VERSION 5.8 ;
BUSBITCHARS "[]" ;
DIVIDERCHAR "/" ;
UNITS
    DATABASE MICRONS 1000 ;
END UNITS

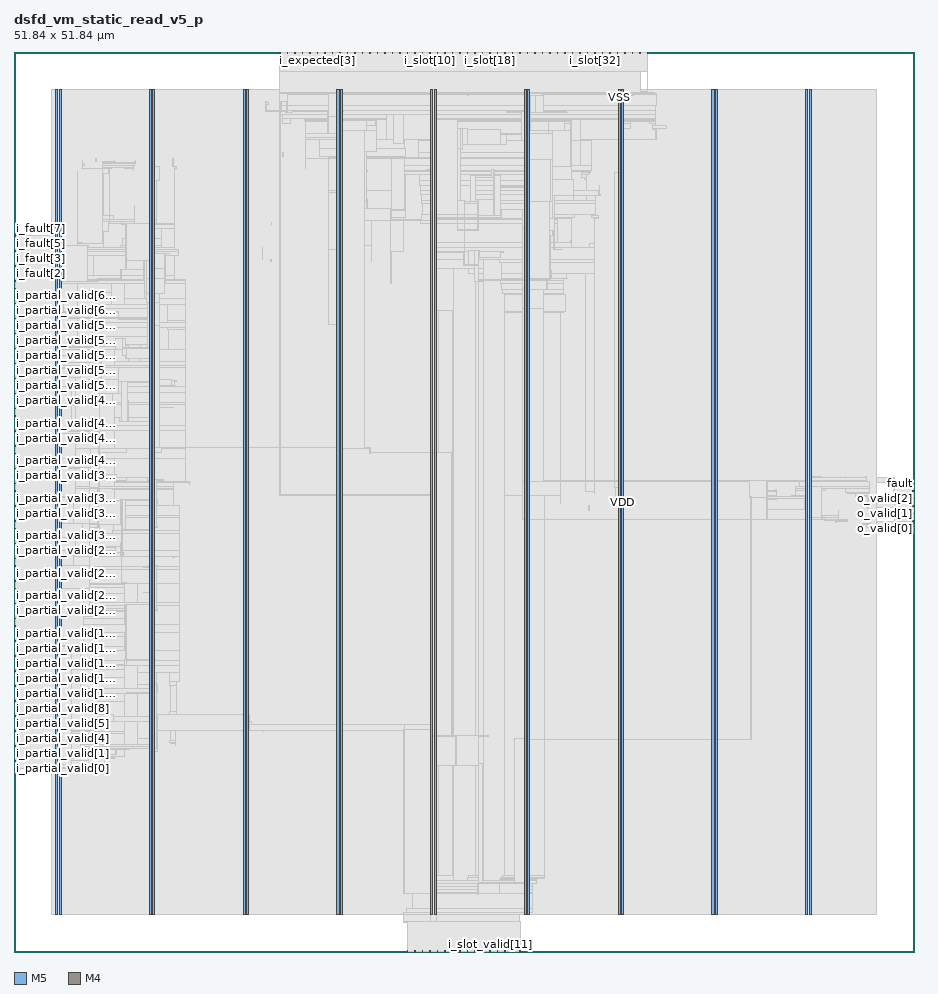
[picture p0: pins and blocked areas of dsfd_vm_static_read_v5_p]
MACRO dsfd_vm_static_read_v5_p
  FOREIGN dsfd_vm_static_read_v5_p 0 0 ;
  CLASS BLOCK ;
  SIZE 51.84 BY 51.84 ;
  PIN ck
    DIRECTION INPUT ;
    USE SIGNAL ;
    PORT
      LAYER M5 ;
        RECT  15.312 51.756 15.336 51.84 ;
    END
  END ck
  PIN fault
    DIRECTION OUTPUT ;
    USE SIGNAL ;
    PORT
      LAYER M4 ;
        RECT  51.756 26.976 51.84 27 ;
    END
  END fault
  PIN i_expected[0]
    DIRECTION INPUT ;
    USE SIGNAL ;
    PORT
      LAYER M5 ;
        RECT  16.176 51.756 16.2 51.84 ;
    END
  END i_expected[0]
  PIN i_expected[1]
    DIRECTION INPUT ;
    USE SIGNAL ;
    PORT
      LAYER M5 ;
        RECT  16.608 51.756 16.632 51.84 ;
    END
  END i_expected[1]
  PIN i_expected[2]
    DIRECTION INPUT ;
    USE SIGNAL ;
    PORT
      LAYER M5 ;
        RECT  17.04 51.756 17.064 51.84 ;
    END
  END i_expected[2]
  PIN i_expected[3]
    DIRECTION INPUT ;
    USE SIGNAL ;
    PORT
      LAYER M5 ;
        RECT  17.472 51.756 17.496 51.84 ;
    END
  END i_expected[3]
  PIN i_expected[4]
    DIRECTION INPUT ;
    USE SIGNAL ;
    PORT
      LAYER M5 ;
        RECT  17.904 51.756 17.928 51.84 ;
    END
  END i_expected[4]
  PIN i_expected[5]
    DIRECTION INPUT ;
    USE SIGNAL ;
    PORT
      LAYER M5 ;
        RECT  18.336 51.756 18.36 51.84 ;
    END
  END i_expected[5]
  PIN i_expected[6]
    DIRECTION INPUT ;
    USE SIGNAL ;
    PORT
      LAYER M5 ;
        RECT  18.768 51.756 18.792 51.84 ;
    END
  END i_expected[6]
  PIN i_expected[7]
    DIRECTION INPUT ;
    USE SIGNAL ;
    PORT
      LAYER M5 ;
        RECT  19.2 51.756 19.224 51.84 ;
    END
  END i_expected[7]
  PIN i_fault[0]
    DIRECTION INPUT ;
    USE SIGNAL ;
    PORT
      LAYER M4 ;
        RECT  0 38.208 0.084 38.232 ;
    END
  END i_fault[0]
  PIN i_fault[1]
    DIRECTION INPUT ;
    USE SIGNAL ;
    PORT
      LAYER M4 ;
        RECT  0 38.64 0.084 38.664 ;
    END
  END i_fault[1]
  PIN i_fault[2]
    DIRECTION INPUT ;
    USE SIGNAL ;
    PORT
      LAYER M4 ;
        RECT  0 39.072 0.084 39.096 ;
    END
  END i_fault[2]
  PIN i_fault[3]
    DIRECTION INPUT ;
    USE SIGNAL ;
    PORT
      LAYER M4 ;
        RECT  0 39.504 0.084 39.528 ;
    END
  END i_fault[3]
  PIN i_fault[4]
    DIRECTION INPUT ;
    USE SIGNAL ;
    PORT
      LAYER M4 ;
        RECT  0 39.936 0.084 39.96 ;
    END
  END i_fault[4]
  PIN i_fault[5]
    DIRECTION INPUT ;
    USE SIGNAL ;
    PORT
      LAYER M4 ;
        RECT  0 40.368 0.084 40.392 ;
    END
  END i_fault[5]
  PIN i_fault[6]
    DIRECTION INPUT ;
    USE SIGNAL ;
    PORT
      LAYER M4 ;
        RECT  0 40.8 0.084 40.824 ;
    END
  END i_fault[6]
  PIN i_fault[7]
    DIRECTION INPUT ;
    USE SIGNAL ;
    PORT
      LAYER M4 ;
        RECT  0 41.232 0.084 41.256 ;
    END
  END i_fault[7]
  PIN i_partial_valid[0]
    DIRECTION INPUT ;
    USE SIGNAL ;
    PORT
      LAYER M4 ;
        RECT  0 10.56 0.084 10.584 ;
    END
  END i_partial_valid[0]
  PIN i_partial_valid[10]
    DIRECTION INPUT ;
    USE SIGNAL ;
    PORT
      LAYER M4 ;
        RECT  0 14.88 0.084 14.904 ;
    END
  END i_partial_valid[10]
  PIN i_partial_valid[11]
    DIRECTION INPUT ;
    USE SIGNAL ;
    PORT
      LAYER M4 ;
        RECT  0 15.312 0.084 15.336 ;
    END
  END i_partial_valid[11]
  PIN i_partial_valid[12]
    DIRECTION INPUT ;
    USE SIGNAL ;
    PORT
      LAYER M4 ;
        RECT  0 15.744 0.084 15.768 ;
    END
  END i_partial_valid[12]
  PIN i_partial_valid[13]
    DIRECTION INPUT ;
    USE SIGNAL ;
    PORT
      LAYER M4 ;
        RECT  0 16.176 0.084 16.2 ;
    END
  END i_partial_valid[13]
  PIN i_partial_valid[14]
    DIRECTION INPUT ;
    USE SIGNAL ;
    PORT
      LAYER M4 ;
        RECT  0 16.608 0.084 16.632 ;
    END
  END i_partial_valid[14]
  PIN i_partial_valid[15]
    DIRECTION INPUT ;
    USE SIGNAL ;
    PORT
      LAYER M4 ;
        RECT  0 17.04 0.084 17.064 ;
    END
  END i_partial_valid[15]
  PIN i_partial_valid[16]
    DIRECTION INPUT ;
    USE SIGNAL ;
    PORT
      LAYER M4 ;
        RECT  0 17.472 0.084 17.496 ;
    END
  END i_partial_valid[16]
  PIN i_partial_valid[17]
    DIRECTION INPUT ;
    USE SIGNAL ;
    PORT
      LAYER M4 ;
        RECT  0 17.904 0.084 17.928 ;
    END
  END i_partial_valid[17]
  PIN i_partial_valid[18]
    DIRECTION INPUT ;
    USE SIGNAL ;
    PORT
      LAYER M4 ;
        RECT  0 18.336 0.084 18.36 ;
    END
  END i_partial_valid[18]
  PIN i_partial_valid[19]
    DIRECTION INPUT ;
    USE SIGNAL ;
    PORT
      LAYER M4 ;
        RECT  0 18.768 0.084 18.792 ;
    END
  END i_partial_valid[19]
  PIN i_partial_valid[1]
    DIRECTION INPUT ;
    USE SIGNAL ;
    PORT
      LAYER M4 ;
        RECT  0 10.992 0.084 11.016 ;
    END
  END i_partial_valid[1]
  PIN i_partial_valid[20]
    DIRECTION INPUT ;
    USE SIGNAL ;
    PORT
      LAYER M4 ;
        RECT  0 19.2 0.084 19.224 ;
    END
  END i_partial_valid[20]
  PIN i_partial_valid[21]
    DIRECTION INPUT ;
    USE SIGNAL ;
    PORT
      LAYER M4 ;
        RECT  0 19.632 0.084 19.656 ;
    END
  END i_partial_valid[21]
  PIN i_partial_valid[22]
    DIRECTION INPUT ;
    USE SIGNAL ;
    PORT
      LAYER M4 ;
        RECT  0 20.064 0.084 20.088 ;
    END
  END i_partial_valid[22]
  PIN i_partial_valid[23]
    DIRECTION INPUT ;
    USE SIGNAL ;
    PORT
      LAYER M4 ;
        RECT  0 20.496 0.084 20.52 ;
    END
  END i_partial_valid[23]
  PIN i_partial_valid[24]
    DIRECTION INPUT ;
    USE SIGNAL ;
    PORT
      LAYER M4 ;
        RECT  0 20.928 0.084 20.952 ;
    END
  END i_partial_valid[24]
  PIN i_partial_valid[25]
    DIRECTION INPUT ;
    USE SIGNAL ;
    PORT
      LAYER M4 ;
        RECT  0 21.36 0.084 21.384 ;
    END
  END i_partial_valid[25]
  PIN i_partial_valid[26]
    DIRECTION INPUT ;
    USE SIGNAL ;
    PORT
      LAYER M4 ;
        RECT  0 21.792 0.084 21.816 ;
    END
  END i_partial_valid[26]
  PIN i_partial_valid[27]
    DIRECTION INPUT ;
    USE SIGNAL ;
    PORT
      LAYER M4 ;
        RECT  0 22.224 0.084 22.248 ;
    END
  END i_partial_valid[27]
  PIN i_partial_valid[28]
    DIRECTION INPUT ;
    USE SIGNAL ;
    PORT
      LAYER M4 ;
        RECT  0 22.656 0.084 22.68 ;
    END
  END i_partial_valid[28]
  PIN i_partial_valid[29]
    DIRECTION INPUT ;
    USE SIGNAL ;
    PORT
      LAYER M4 ;
        RECT  0 23.088 0.084 23.112 ;
    END
  END i_partial_valid[29]
  PIN i_partial_valid[2]
    DIRECTION INPUT ;
    USE SIGNAL ;
    PORT
      LAYER M4 ;
        RECT  0 11.424 0.084 11.448 ;
    END
  END i_partial_valid[2]
  PIN i_partial_valid[30]
    DIRECTION INPUT ;
    USE SIGNAL ;
    PORT
      LAYER M4 ;
        RECT  0 23.52 0.084 23.544 ;
    END
  END i_partial_valid[30]
  PIN i_partial_valid[31]
    DIRECTION INPUT ;
    USE SIGNAL ;
    PORT
      LAYER M4 ;
        RECT  0 23.952 0.084 23.976 ;
    END
  END i_partial_valid[31]
  PIN i_partial_valid[32]
    DIRECTION INPUT ;
    USE SIGNAL ;
    PORT
      LAYER M4 ;
        RECT  0 24.384 0.084 24.408 ;
    END
  END i_partial_valid[32]
  PIN i_partial_valid[33]
    DIRECTION INPUT ;
    USE SIGNAL ;
    PORT
      LAYER M4 ;
        RECT  0 24.816 0.084 24.84 ;
    END
  END i_partial_valid[33]
  PIN i_partial_valid[34]
    DIRECTION INPUT ;
    USE SIGNAL ;
    PORT
      LAYER M4 ;
        RECT  0 25.248 0.084 25.272 ;
    END
  END i_partial_valid[34]
  PIN i_partial_valid[35]
    DIRECTION INPUT ;
    USE SIGNAL ;
    PORT
      LAYER M4 ;
        RECT  0 25.68 0.084 25.704 ;
    END
  END i_partial_valid[35]
  PIN i_partial_valid[36]
    DIRECTION INPUT ;
    USE SIGNAL ;
    PORT
      LAYER M4 ;
        RECT  0 26.112 0.084 26.136 ;
    END
  END i_partial_valid[36]
  PIN i_partial_valid[37]
    DIRECTION INPUT ;
    USE SIGNAL ;
    PORT
      LAYER M4 ;
        RECT  0 26.544 0.084 26.568 ;
    END
  END i_partial_valid[37]
  PIN i_partial_valid[38]
    DIRECTION INPUT ;
    USE SIGNAL ;
    PORT
      LAYER M4 ;
        RECT  0 26.976 0.084 27 ;
    END
  END i_partial_valid[38]
  PIN i_partial_valid[39]
    DIRECTION INPUT ;
    USE SIGNAL ;
    PORT
      LAYER M4 ;
        RECT  0 27.408 0.084 27.432 ;
    END
  END i_partial_valid[39]
  PIN i_partial_valid[3]
    DIRECTION INPUT ;
    USE SIGNAL ;
    PORT
      LAYER M4 ;
        RECT  0 11.856 0.084 11.88 ;
    END
  END i_partial_valid[3]
  PIN i_partial_valid[40]
    DIRECTION INPUT ;
    USE SIGNAL ;
    PORT
      LAYER M4 ;
        RECT  0 27.84 0.084 27.864 ;
    END
  END i_partial_valid[40]
  PIN i_partial_valid[41]
    DIRECTION INPUT ;
    USE SIGNAL ;
    PORT
      LAYER M4 ;
        RECT  0 28.272 0.084 28.296 ;
    END
  END i_partial_valid[41]
  PIN i_partial_valid[42]
    DIRECTION INPUT ;
    USE SIGNAL ;
    PORT
      LAYER M4 ;
        RECT  0 28.704 0.084 28.728 ;
    END
  END i_partial_valid[42]
  PIN i_partial_valid[43]
    DIRECTION INPUT ;
    USE SIGNAL ;
    PORT
      LAYER M4 ;
        RECT  0 29.136 0.084 29.16 ;
    END
  END i_partial_valid[43]
  PIN i_partial_valid[44]
    DIRECTION INPUT ;
    USE SIGNAL ;
    PORT
      LAYER M4 ;
        RECT  0 29.568 0.084 29.592 ;
    END
  END i_partial_valid[44]
  PIN i_partial_valid[45]
    DIRECTION INPUT ;
    USE SIGNAL ;
    PORT
      LAYER M4 ;
        RECT  0 30 0.084 30.024 ;
    END
  END i_partial_valid[45]
  PIN i_partial_valid[46]
    DIRECTION INPUT ;
    USE SIGNAL ;
    PORT
      LAYER M4 ;
        RECT  0 30.432 0.084 30.456 ;
    END
  END i_partial_valid[46]
  PIN i_partial_valid[47]
    DIRECTION INPUT ;
    USE SIGNAL ;
    PORT
      LAYER M4 ;
        RECT  0 30.864 0.084 30.888 ;
    END
  END i_partial_valid[47]
  PIN i_partial_valid[48]
    DIRECTION INPUT ;
    USE SIGNAL ;
    PORT
      LAYER M4 ;
        RECT  0 31.296 0.084 31.32 ;
    END
  END i_partial_valid[48]
  PIN i_partial_valid[49]
    DIRECTION INPUT ;
    USE SIGNAL ;
    PORT
      LAYER M4 ;
        RECT  0 31.728 0.084 31.752 ;
    END
  END i_partial_valid[49]
  PIN i_partial_valid[4]
    DIRECTION INPUT ;
    USE SIGNAL ;
    PORT
      LAYER M4 ;
        RECT  0 12.288 0.084 12.312 ;
    END
  END i_partial_valid[4]
  PIN i_partial_valid[50]
    DIRECTION INPUT ;
    USE SIGNAL ;
    PORT
      LAYER M4 ;
        RECT  0 32.16 0.084 32.184 ;
    END
  END i_partial_valid[50]
  PIN i_partial_valid[51]
    DIRECTION INPUT ;
    USE SIGNAL ;
    PORT
      LAYER M4 ;
        RECT  0 32.592 0.084 32.616 ;
    END
  END i_partial_valid[51]
  PIN i_partial_valid[52]
    DIRECTION INPUT ;
    USE SIGNAL ;
    PORT
      LAYER M4 ;
        RECT  0 33.024 0.084 33.048 ;
    END
  END i_partial_valid[52]
  PIN i_partial_valid[53]
    DIRECTION INPUT ;
    USE SIGNAL ;
    PORT
      LAYER M4 ;
        RECT  0 33.456 0.084 33.48 ;
    END
  END i_partial_valid[53]
  PIN i_partial_valid[54]
    DIRECTION INPUT ;
    USE SIGNAL ;
    PORT
      LAYER M4 ;
        RECT  0 33.888 0.084 33.912 ;
    END
  END i_partial_valid[54]
  PIN i_partial_valid[55]
    DIRECTION INPUT ;
    USE SIGNAL ;
    PORT
      LAYER M4 ;
        RECT  0 34.32 0.084 34.344 ;
    END
  END i_partial_valid[55]
  PIN i_partial_valid[56]
    DIRECTION INPUT ;
    USE SIGNAL ;
    PORT
      LAYER M4 ;
        RECT  0 34.752 0.084 34.776 ;
    END
  END i_partial_valid[56]
  PIN i_partial_valid[57]
    DIRECTION INPUT ;
    USE SIGNAL ;
    PORT
      LAYER M4 ;
        RECT  0 35.184 0.084 35.208 ;
    END
  END i_partial_valid[57]
  PIN i_partial_valid[58]
    DIRECTION INPUT ;
    USE SIGNAL ;
    PORT
      LAYER M4 ;
        RECT  0 35.616 0.084 35.64 ;
    END
  END i_partial_valid[58]
  PIN i_partial_valid[59]
    DIRECTION INPUT ;
    USE SIGNAL ;
    PORT
      LAYER M4 ;
        RECT  0 36.048 0.084 36.072 ;
    END
  END i_partial_valid[59]
  PIN i_partial_valid[5]
    DIRECTION INPUT ;
    USE SIGNAL ;
    PORT
      LAYER M4 ;
        RECT  0 12.72 0.084 12.744 ;
    END
  END i_partial_valid[5]
  PIN i_partial_valid[60]
    DIRECTION INPUT ;
    USE SIGNAL ;
    PORT
      LAYER M4 ;
        RECT  0 36.48 0.084 36.504 ;
    END
  END i_partial_valid[60]
  PIN i_partial_valid[61]
    DIRECTION INPUT ;
    USE SIGNAL ;
    PORT
      LAYER M4 ;
        RECT  0 36.912 0.084 36.936 ;
    END
  END i_partial_valid[61]
  PIN i_partial_valid[62]
    DIRECTION INPUT ;
    USE SIGNAL ;
    PORT
      LAYER M4 ;
        RECT  0 37.344 0.084 37.368 ;
    END
  END i_partial_valid[62]
  PIN i_partial_valid[63]
    DIRECTION INPUT ;
    USE SIGNAL ;
    PORT
      LAYER M4 ;
        RECT  0 37.776 0.084 37.8 ;
    END
  END i_partial_valid[63]
  PIN i_partial_valid[6]
    DIRECTION INPUT ;
    USE SIGNAL ;
    PORT
      LAYER M4 ;
        RECT  0 13.152 0.084 13.176 ;
    END
  END i_partial_valid[6]
  PIN i_partial_valid[7]
    DIRECTION INPUT ;
    USE SIGNAL ;
    PORT
      LAYER M4 ;
        RECT  0 13.584 0.084 13.608 ;
    END
  END i_partial_valid[7]
  PIN i_partial_valid[8]
    DIRECTION INPUT ;
    USE SIGNAL ;
    PORT
      LAYER M4 ;
        RECT  0 14.016 0.084 14.04 ;
    END
  END i_partial_valid[8]
  PIN i_partial_valid[9]
    DIRECTION INPUT ;
    USE SIGNAL ;
    PORT
      LAYER M4 ;
        RECT  0 14.448 0.084 14.472 ;
    END
  END i_partial_valid[9]
  PIN i_slot[0]
    DIRECTION INPUT ;
    USE SIGNAL ;
    PORT
      LAYER M5 ;
        RECT  19.632 51.756 19.656 51.84 ;
    END
  END i_slot[0]
  PIN i_slot[10]
    DIRECTION INPUT ;
    USE SIGNAL ;
    PORT
      LAYER M5 ;
        RECT  23.952 51.756 23.976 51.84 ;
    END
  END i_slot[10]
  PIN i_slot[11]
    DIRECTION INPUT ;
    USE SIGNAL ;
    PORT
      LAYER M5 ;
        RECT  24.384 51.756 24.408 51.84 ;
    END
  END i_slot[11]
  PIN i_slot[12]
    DIRECTION INPUT ;
    USE SIGNAL ;
    PORT
      LAYER M5 ;
        RECT  24.816 51.756 24.84 51.84 ;
    END
  END i_slot[12]
  PIN i_slot[13]
    DIRECTION INPUT ;
    USE SIGNAL ;
    PORT
      LAYER M5 ;
        RECT  25.248 51.756 25.272 51.84 ;
    END
  END i_slot[13]
  PIN i_slot[14]
    DIRECTION INPUT ;
    USE SIGNAL ;
    PORT
      LAYER M5 ;
        RECT  25.68 51.756 25.704 51.84 ;
    END
  END i_slot[14]
  PIN i_slot[15]
    DIRECTION INPUT ;
    USE SIGNAL ;
    PORT
      LAYER M5 ;
        RECT  26.112 51.756 26.136 51.84 ;
    END
  END i_slot[15]
  PIN i_slot[16]
    DIRECTION INPUT ;
    USE SIGNAL ;
    PORT
      LAYER M5 ;
        RECT  26.544 51.756 26.568 51.84 ;
    END
  END i_slot[16]
  PIN i_slot[17]
    DIRECTION INPUT ;
    USE SIGNAL ;
    PORT
      LAYER M5 ;
        RECT  26.976 51.756 27 51.84 ;
    END
  END i_slot[17]
  PIN i_slot[18]
    DIRECTION INPUT ;
    USE SIGNAL ;
    PORT
      LAYER M5 ;
        RECT  27.408 51.756 27.432 51.84 ;
    END
  END i_slot[18]
  PIN i_slot[19]
    DIRECTION INPUT ;
    USE SIGNAL ;
    PORT
      LAYER M5 ;
        RECT  27.84 51.756 27.864 51.84 ;
    END
  END i_slot[19]
  PIN i_slot[1]
    DIRECTION INPUT ;
    USE SIGNAL ;
    PORT
      LAYER M5 ;
        RECT  20.064 51.756 20.088 51.84 ;
    END
  END i_slot[1]
  PIN i_slot[20]
    DIRECTION INPUT ;
    USE SIGNAL ;
    PORT
      LAYER M5 ;
        RECT  28.272 51.756 28.296 51.84 ;
    END
  END i_slot[20]
  PIN i_slot[21]
    DIRECTION INPUT ;
    USE SIGNAL ;
    PORT
      LAYER M5 ;
        RECT  28.704 51.756 28.728 51.84 ;
    END
  END i_slot[21]
  PIN i_slot[22]
    DIRECTION INPUT ;
    USE SIGNAL ;
    PORT
      LAYER M5 ;
        RECT  29.136 51.756 29.16 51.84 ;
    END
  END i_slot[22]
  PIN i_slot[23]
    DIRECTION INPUT ;
    USE SIGNAL ;
    PORT
      LAYER M5 ;
        RECT  29.568 51.756 29.592 51.84 ;
    END
  END i_slot[23]
  PIN i_slot[24]
    DIRECTION INPUT ;
    USE SIGNAL ;
    PORT
      LAYER M5 ;
        RECT  30 51.756 30.024 51.84 ;
    END
  END i_slot[24]
  PIN i_slot[25]
    DIRECTION INPUT ;
    USE SIGNAL ;
    PORT
      LAYER M5 ;
        RECT  30.432 51.756 30.456 51.84 ;
    END
  END i_slot[25]
  PIN i_slot[26]
    DIRECTION INPUT ;
    USE SIGNAL ;
    PORT
      LAYER M5 ;
        RECT  30.864 51.756 30.888 51.84 ;
    END
  END i_slot[26]
  PIN i_slot[27]
    DIRECTION INPUT ;
    USE SIGNAL ;
    PORT
      LAYER M5 ;
        RECT  31.296 51.756 31.32 51.84 ;
    END
  END i_slot[27]
  PIN i_slot[28]
    DIRECTION INPUT ;
    USE SIGNAL ;
    PORT
      LAYER M5 ;
        RECT  31.728 51.756 31.752 51.84 ;
    END
  END i_slot[28]
  PIN i_slot[29]
    DIRECTION INPUT ;
    USE SIGNAL ;
    PORT
      LAYER M5 ;
        RECT  32.16 51.756 32.184 51.84 ;
    END
  END i_slot[29]
  PIN i_slot[2]
    DIRECTION INPUT ;
    USE SIGNAL ;
    PORT
      LAYER M5 ;
        RECT  20.496 51.756 20.52 51.84 ;
    END
  END i_slot[2]
  PIN i_slot[30]
    DIRECTION INPUT ;
    USE SIGNAL ;
    PORT
      LAYER M5 ;
        RECT  32.592 51.756 32.616 51.84 ;
    END
  END i_slot[30]
  PIN i_slot[31]
    DIRECTION INPUT ;
    USE SIGNAL ;
    PORT
      LAYER M5 ;
        RECT  33.024 51.756 33.048 51.84 ;
    END
  END i_slot[31]
  PIN i_slot[32]
    DIRECTION INPUT ;
    USE SIGNAL ;
    PORT
      LAYER M5 ;
        RECT  33.456 51.756 33.48 51.84 ;
    END
  END i_slot[32]
  PIN i_slot[33]
    DIRECTION INPUT ;
    USE SIGNAL ;
    PORT
      LAYER M5 ;
        RECT  33.888 51.756 33.912 51.84 ;
    END
  END i_slot[33]
  PIN i_slot[34]
    DIRECTION INPUT ;
    USE SIGNAL ;
    PORT
      LAYER M5 ;
        RECT  34.32 51.756 34.344 51.84 ;
    END
  END i_slot[34]
  PIN i_slot[35]
    DIRECTION INPUT ;
    USE SIGNAL ;
    PORT
      LAYER M5 ;
        RECT  34.752 51.756 34.776 51.84 ;
    END
  END i_slot[35]
  PIN i_slot[36]
    DIRECTION INPUT ;
    USE SIGNAL ;
    PORT
      LAYER M5 ;
        RECT  35.184 51.756 35.208 51.84 ;
    END
  END i_slot[36]
  PIN i_slot[37]
    DIRECTION INPUT ;
    USE SIGNAL ;
    PORT
      LAYER M5 ;
        RECT  35.616 51.756 35.64 51.84 ;
    END
  END i_slot[37]
  PIN i_slot[38]
    DIRECTION INPUT ;
    USE SIGNAL ;
    PORT
      LAYER M5 ;
        RECT  36.048 51.756 36.072 51.84 ;
    END
  END i_slot[38]
  PIN i_slot[39]
    DIRECTION INPUT ;
    USE SIGNAL ;
    PORT
      LAYER M5 ;
        RECT  36.48 51.756 36.504 51.84 ;
    END
  END i_slot[39]
  PIN i_slot[3]
    DIRECTION INPUT ;
    USE SIGNAL ;
    PORT
      LAYER M5 ;
        RECT  20.928 51.756 20.952 51.84 ;
    END
  END i_slot[3]
  PIN i_slot[4]
    DIRECTION INPUT ;
    USE SIGNAL ;
    PORT
      LAYER M5 ;
        RECT  21.36 51.756 21.384 51.84 ;
    END
  END i_slot[4]
  PIN i_slot[5]
    DIRECTION INPUT ;
    USE SIGNAL ;
    PORT
      LAYER M5 ;
        RECT  21.792 51.756 21.816 51.84 ;
    END
  END i_slot[5]
  PIN i_slot[6]
    DIRECTION INPUT ;
    USE SIGNAL ;
    PORT
      LAYER M5 ;
        RECT  22.224 51.756 22.248 51.84 ;
    END
  END i_slot[6]
  PIN i_slot[7]
    DIRECTION INPUT ;
    USE SIGNAL ;
    PORT
      LAYER M5 ;
        RECT  22.656 51.756 22.68 51.84 ;
    END
  END i_slot[7]
  PIN i_slot[8]
    DIRECTION INPUT ;
    USE SIGNAL ;
    PORT
      LAYER M5 ;
        RECT  23.088 51.756 23.112 51.84 ;
    END
  END i_slot[8]
  PIN i_slot[9]
    DIRECTION INPUT ;
    USE SIGNAL ;
    PORT
      LAYER M5 ;
        RECT  23.52 51.756 23.544 51.84 ;
    END
  END i_slot[9]
  PIN i_slot_valid[0]
    DIRECTION INPUT ;
    USE SIGNAL ;
    PORT
      LAYER M5 ;
        RECT  22.656 0 22.68 0.084 ;
    END
  END i_slot_valid[0]
  PIN i_slot_valid[10]
    DIRECTION INPUT ;
    USE SIGNAL ;
    PORT
      LAYER M5 ;
        RECT  26.976 0 27 0.084 ;
    END
  END i_slot_valid[10]
  PIN i_slot_valid[11]
    DIRECTION INPUT ;
    USE SIGNAL ;
    PORT
      LAYER M5 ;
        RECT  27.408 0 27.432 0.084 ;
    END
  END i_slot_valid[11]
  PIN i_slot_valid[12]
    DIRECTION INPUT ;
    USE SIGNAL ;
    PORT
      LAYER M5 ;
        RECT  27.84 0 27.864 0.084 ;
    END
  END i_slot_valid[12]
  PIN i_slot_valid[13]
    DIRECTION INPUT ;
    USE SIGNAL ;
    PORT
      LAYER M5 ;
        RECT  28.272 0 28.296 0.084 ;
    END
  END i_slot_valid[13]
  PIN i_slot_valid[14]
    DIRECTION INPUT ;
    USE SIGNAL ;
    PORT
      LAYER M5 ;
        RECT  28.704 0 28.728 0.084 ;
    END
  END i_slot_valid[14]
  PIN i_slot_valid[15]
    DIRECTION INPUT ;
    USE SIGNAL ;
    PORT
      LAYER M5 ;
        RECT  29.136 0 29.16 0.084 ;
    END
  END i_slot_valid[15]
  PIN i_slot_valid[1]
    DIRECTION INPUT ;
    USE SIGNAL ;
    PORT
      LAYER M5 ;
        RECT  23.088 0 23.112 0.084 ;
    END
  END i_slot_valid[1]
  PIN i_slot_valid[2]
    DIRECTION INPUT ;
    USE SIGNAL ;
    PORT
      LAYER M5 ;
        RECT  23.52 0 23.544 0.084 ;
    END
  END i_slot_valid[2]
  PIN i_slot_valid[3]
    DIRECTION INPUT ;
    USE SIGNAL ;
    PORT
      LAYER M5 ;
        RECT  23.952 0 23.976 0.084 ;
    END
  END i_slot_valid[3]
  PIN i_slot_valid[4]
    DIRECTION INPUT ;
    USE SIGNAL ;
    PORT
      LAYER M5 ;
        RECT  24.384 0 24.408 0.084 ;
    END
  END i_slot_valid[4]
  PIN i_slot_valid[5]
    DIRECTION INPUT ;
    USE SIGNAL ;
    PORT
      LAYER M5 ;
        RECT  24.816 0 24.84 0.084 ;
    END
  END i_slot_valid[5]
  PIN i_slot_valid[6]
    DIRECTION INPUT ;
    USE SIGNAL ;
    PORT
      LAYER M5 ;
        RECT  25.248 0 25.272 0.084 ;
    END
  END i_slot_valid[6]
  PIN i_slot_valid[7]
    DIRECTION INPUT ;
    USE SIGNAL ;
    PORT
      LAYER M5 ;
        RECT  25.68 0 25.704 0.084 ;
    END
  END i_slot_valid[7]
  PIN i_slot_valid[8]
    DIRECTION INPUT ;
    USE SIGNAL ;
    PORT
      LAYER M5 ;
        RECT  26.112 0 26.136 0.084 ;
    END
  END i_slot_valid[8]
  PIN i_slot_valid[9]
    DIRECTION INPUT ;
    USE SIGNAL ;
    PORT
      LAYER M5 ;
        RECT  26.544 0 26.568 0.084 ;
    END
  END i_slot_valid[9]
  PIN o_valid[0]
    DIRECTION OUTPUT ;
    USE SIGNAL ;
    PORT
      LAYER M4 ;
        RECT  51.756 24.816 51.84 24.84 ;
    END
  END o_valid[0]
  PIN o_valid[1]
    DIRECTION OUTPUT ;
    USE SIGNAL ;
    PORT
      LAYER M4 ;
        RECT  51.756 25.248 51.84 25.272 ;
    END
  END o_valid[1]
  PIN o_valid[2]
    DIRECTION OUTPUT ;
    USE SIGNAL ;
    PORT
      LAYER M4 ;
        RECT  51.756 25.68 51.84 25.704 ;
    END
  END o_valid[2]
  PIN o_valid[3]
    DIRECTION OUTPUT ;
    USE SIGNAL ;
    PORT
      LAYER M4 ;
        RECT  51.756 26.112 51.84 26.136 ;
    END
  END o_valid[3]
  PIN o_valid[4]
    DIRECTION OUTPUT ;
    USE SIGNAL ;
    PORT
      LAYER M4 ;
        RECT  51.756 26.544 51.84 26.568 ;
    END
  END o_valid[4]
  PIN rst_n
    DIRECTION INPUT ;
    USE SIGNAL ;
    PORT
      LAYER M5 ;
        RECT  15.744 51.756 15.768 51.84 ;
    END
  END rst_n
  PIN VDD
    DIRECTION INOUT ;
    USE POWER ;
    PORT
      LAYER M5 ;
        RECT  45.792 2.151 45.912 49.689 ;
        RECT  40.392 2.151 40.512 49.689 ;
        RECT  34.992 2.151 35.112 49.689 ;
        RECT  29.592 2.151 29.712 49.689 ;
        RECT  24.192 2.151 24.312 49.689 ;
        RECT  18.792 2.151 18.912 49.689 ;
        RECT  13.392 2.151 13.512 49.689 ;
        RECT  7.992 2.151 8.112 49.689 ;
        RECT  2.592 2.151 2.712 49.689 ;
    END
  END VDD
  PIN VSS
    DIRECTION INOUT ;
    USE GROUND ;
    PORT
      LAYER M5 ;
        RECT  45.6 2.137 45.72 49.703 ;
        RECT  40.2 2.137 40.32 49.703 ;
        RECT  34.8 2.137 34.92 49.703 ;
        RECT  29.4 2.137 29.52 49.703 ;
        RECT  24 2.137 24.12 49.703 ;
        RECT  18.6 2.137 18.72 49.703 ;
        RECT  13.2 2.137 13.32 49.703 ;
        RECT  7.8 2.137 7.92 49.703 ;
        RECT  2.4 2.137 2.52 49.703 ;
    END
  END VSS
  # OT_OBS_CLOSED layer=M5 d_um=1.536 added=35
  OBS
    LAYER RVTN ;
     RECT  2.16 2.16 49.68 2.295 ;
     RECT  2.16 2.565 49.68 2.835 ;
     RECT  2.16 3.105 49.68 3.375 ;
     RECT  2.16 3.645 49.68 3.915 ;
     RECT  2.16 4.185 49.68 4.455 ;
     RECT  2.16 4.725 49.68 4.995 ;
     RECT  2.16 5.265 49.68 5.535 ;
     RECT  2.16 5.805 49.68 6.075 ;
     RECT  2.16 6.345 49.68 6.615 ;
     RECT  2.16 6.885 49.68 7.155 ;
     RECT  2.16 7.425 49.68 7.695 ;
     RECT  2.16 7.965 49.68 8.235 ;
     RECT  2.16 8.505 49.68 8.775 ;
     RECT  2.16 9.045 49.68 9.315 ;
     RECT  2.16 9.585 49.68 9.855 ;
     RECT  2.16 10.125 49.68 10.395 ;
     RECT  2.16 10.665 49.68 10.935 ;
     RECT  2.16 11.205 49.68 11.475 ;
     RECT  2.16 11.745 49.68 12.015 ;
     RECT  2.16 12.285 49.68 12.555 ;
     RECT  2.16 12.825 49.68 13.095 ;
     RECT  2.16 13.365 49.68 13.635 ;
     RECT  2.16 13.905 49.68 14.175 ;
     RECT  2.16 14.445 49.68 14.715 ;
     RECT  2.16 14.985 49.68 15.255 ;
     RECT  2.16 15.525 49.68 15.795 ;
     RECT  2.16 16.065 49.68 16.335 ;
     RECT  2.16 16.605 49.68 16.875 ;
     RECT  2.16 17.145 49.68 17.415 ;
     RECT  2.16 17.685 49.68 17.955 ;
     RECT  2.16 18.225 49.68 18.495 ;
     RECT  2.16 18.765 49.68 19.035 ;
     RECT  2.16 19.305 49.68 19.575 ;
     RECT  2.16 19.845 49.68 20.115 ;
     RECT  2.16 20.385 49.68 20.655 ;
     RECT  2.16 20.925 49.68 21.195 ;
     RECT  2.16 21.465 49.68 21.735 ;
     RECT  2.16 22.005 49.68 22.275 ;
     RECT  2.16 22.545 49.68 22.815 ;
     RECT  2.16 23.085 49.68 23.355 ;
     RECT  2.16 23.625 49.68 23.895 ;
     RECT  2.16 24.165 49.68 24.435 ;
     RECT  2.16 24.705 49.68 24.975 ;
     RECT  2.16 25.245 49.68 25.515 ;
     RECT  2.16 25.785 49.68 26.055 ;
     RECT  2.16 26.325 49.68 26.595 ;
     RECT  2.16 26.865 49.68 27.135 ;
     RECT  2.16 27.405 49.68 27.675 ;
     RECT  2.16 27.945 49.68 28.215 ;
     RECT  2.16 28.485 49.68 28.755 ;
     RECT  2.16 29.025 49.68 29.295 ;
     RECT  2.16 29.565 49.68 29.835 ;
     RECT  2.16 30.105 49.68 30.375 ;
     RECT  2.16 30.645 49.68 30.915 ;
     RECT  2.16 31.185 49.68 31.455 ;
     RECT  2.16 31.725 49.68 31.995 ;
     RECT  2.16 32.265 49.68 32.535 ;
     RECT  2.16 32.805 49.68 33.075 ;
     RECT  2.16 33.345 49.68 33.615 ;
     RECT  2.16 33.885 49.68 34.155 ;
     RECT  2.16 34.425 49.68 34.695 ;
     RECT  2.16 34.965 49.68 35.235 ;
     RECT  2.16 35.505 49.68 35.775 ;
     RECT  2.16 36.045 49.68 36.315 ;
     RECT  2.16 36.585 49.68 36.855 ;
     RECT  2.16 37.125 49.68 37.395 ;
     RECT  2.16 37.665 49.68 37.935 ;
     RECT  2.16 38.205 49.68 38.475 ;
     RECT  2.16 38.745 49.68 39.015 ;
     RECT  2.16 39.285 49.68 39.555 ;
     RECT  2.16 39.825 49.68 40.095 ;
     RECT  2.16 40.365 49.68 40.635 ;
     RECT  2.16 40.905 49.68 41.175 ;
     RECT  2.16 41.445 49.68 41.715 ;
     RECT  2.16 41.985 49.68 42.255 ;
     RECT  2.16 42.525 49.68 42.795 ;
     RECT  2.16 43.065 49.68 43.335 ;
     RECT  2.16 43.605 49.68 43.875 ;
     RECT  2.16 44.145 49.68 44.415 ;
     RECT  2.16 44.685 49.68 44.955 ;
     RECT  2.16 45.225 49.68 45.495 ;
     RECT  2.16 45.765 49.68 46.035 ;
     RECT  2.16 46.305 49.68 46.575 ;
     RECT  2.16 46.845 49.68 47.115 ;
     RECT  2.16 47.385 49.68 47.655 ;
     RECT  2.16 47.925 49.68 48.195 ;
     RECT  2.16 48.465 49.68 48.735 ;
     RECT  2.16 49.005 49.68 49.275 ;
     RECT  2.16 49.545 49.68 49.68 ;
    LAYER RVTP ;
     RECT  2.16 2.295 49.68 2.565 ;
     RECT  2.16 2.835 49.68 3.105 ;
     RECT  2.16 3.375 49.68 3.645 ;
     RECT  2.16 3.915 49.68 4.185 ;
     RECT  2.16 4.455 49.68 4.725 ;
     RECT  2.16 4.995 49.68 5.265 ;
     RECT  2.16 5.535 49.68 5.805 ;
     RECT  2.16 6.075 49.68 6.345 ;
     RECT  2.16 6.615 49.68 6.885 ;
     RECT  2.16 7.155 49.68 7.425 ;
     RECT  2.16 7.695 49.68 7.965 ;
     RECT  2.16 8.235 49.68 8.505 ;
     RECT  2.16 8.775 49.68 9.045 ;
     RECT  2.16 9.315 49.68 9.585 ;
     RECT  2.16 9.855 49.68 10.125 ;
     RECT  2.16 10.395 49.68 10.665 ;
     RECT  2.16 10.935 49.68 11.205 ;
     RECT  2.16 11.475 49.68 11.745 ;
     RECT  2.16 12.015 49.68 12.285 ;
     RECT  2.16 12.555 49.68 12.825 ;
     RECT  2.16 13.095 49.68 13.365 ;
     RECT  2.16 13.635 49.68 13.905 ;
     RECT  2.16 14.175 49.68 14.445 ;
     RECT  2.16 14.715 49.68 14.985 ;
     RECT  2.16 15.255 49.68 15.525 ;
     RECT  2.16 15.795 49.68 16.065 ;
     RECT  2.16 16.335 49.68 16.605 ;
     RECT  2.16 16.875 49.68 17.145 ;
     RECT  2.16 17.415 49.68 17.685 ;
     RECT  2.16 17.955 49.68 18.225 ;
     RECT  2.16 18.495 49.68 18.765 ;
     RECT  2.16 19.035 49.68 19.305 ;
     RECT  2.16 19.575 49.68 19.845 ;
     RECT  2.16 20.115 49.68 20.385 ;
     RECT  2.16 20.655 49.68 20.925 ;
     RECT  2.16 21.195 49.68 21.465 ;
     RECT  2.16 21.735 49.68 22.005 ;
     RECT  2.16 22.275 49.68 22.545 ;
     RECT  2.16 22.815 49.68 23.085 ;
     RECT  2.16 23.355 49.68 23.625 ;
     RECT  2.16 23.895 49.68 24.165 ;
     RECT  2.16 24.435 49.68 24.705 ;
     RECT  2.16 24.975 49.68 25.245 ;
     RECT  2.16 25.515 49.68 25.785 ;
     RECT  2.16 26.055 49.68 26.325 ;
     RECT  2.16 26.595 49.68 26.865 ;
     RECT  2.16 27.135 49.68 27.405 ;
     RECT  2.16 27.675 49.68 27.945 ;
     RECT  2.16 28.215 49.68 28.485 ;
     RECT  2.16 28.755 49.68 29.025 ;
     RECT  2.16 29.295 49.68 29.565 ;
     RECT  2.16 29.835 49.68 30.105 ;
     RECT  2.16 30.375 49.68 30.645 ;
     RECT  2.16 30.915 49.68 31.185 ;
     RECT  2.16 31.455 49.68 31.725 ;
     RECT  2.16 31.995 49.68 32.265 ;
     RECT  2.16 32.535 49.68 32.805 ;
     RECT  2.16 33.075 49.68 33.345 ;
     RECT  2.16 33.615 49.68 33.885 ;
     RECT  2.16 34.155 49.68 34.425 ;
     RECT  2.16 34.695 49.68 34.965 ;
     RECT  2.16 35.235 49.68 35.505 ;
     RECT  2.16 35.775 49.68 36.045 ;
     RECT  2.16 36.315 49.68 36.585 ;
     RECT  2.16 36.855 49.68 37.125 ;
     RECT  2.16 37.395 49.68 37.665 ;
     RECT  2.16 37.935 49.68 38.205 ;
     RECT  2.16 38.475 49.68 38.745 ;
     RECT  2.16 39.015 49.68 39.285 ;
     RECT  2.16 39.555 49.68 39.825 ;
     RECT  2.16 40.095 49.68 40.365 ;
     RECT  2.16 40.635 49.68 40.905 ;
     RECT  2.16 41.175 49.68 41.445 ;
     RECT  2.16 41.715 49.68 41.985 ;
     RECT  2.16 42.255 49.68 42.525 ;
     RECT  2.16 42.795 49.68 43.065 ;
     RECT  2.16 43.335 49.68 43.605 ;
     RECT  2.16 43.875 49.68 44.145 ;
     RECT  2.16 44.415 49.68 44.685 ;
     RECT  2.16 44.955 49.68 45.225 ;
     RECT  2.16 45.495 49.68 45.765 ;
     RECT  2.16 46.035 49.68 46.305 ;
     RECT  2.16 46.575 49.68 46.845 ;
     RECT  2.16 47.115 49.68 47.385 ;
     RECT  2.16 47.655 49.68 47.925 ;
     RECT  2.16 48.195 49.68 48.465 ;
     RECT  2.16 48.735 49.68 49.005 ;
     RECT  2.16 49.275 49.68 49.545 ;
    LAYER M1 ;
     RECT  2.16 2.151 49.68 49.689 ;
    LAYER M2 ;
     RECT  0.103 22.212 2.16 22.23 ;
     RECT  0.103 23.904 2.16 23.922 ;
     RECT  0.103 27.342 2.16 27.36 ;
     RECT  2.16 2.151 49.68 49.689 ;
     RECT  49.68 27.036 50.675 27.324 ;
     RECT  49.68 25.596 50.711 26.244 ;
     RECT  50.675 27.306 50.711 27.324 ;
     RECT  49.68 24.48 50.747 24.804 ;
     RECT  50.711 25.596 50.747 25.614 ;
     RECT  50.747 24.786 50.783 24.804 ;
    LAYER M3 ;
     RECT  23.94 0.571 23.958 1.723 ;
     RECT  22.428 1.723 29.142 2.143 ;
     RECT  22.428 2.143 29.505 2.255 ;
     RECT  22.608 2.255 29.505 2.263 ;
     RECT  2.415 2.143 2.505 2.413 ;
     RECT  7.815 2.143 7.905 2.413 ;
     RECT  13.215 2.143 13.305 2.413 ;
     RECT  18.615 2.143 18.705 2.413 ;
     RECT  34.815 2.143 34.905 2.413 ;
     RECT  40.215 2.143 40.305 2.413 ;
     RECT  45.615 2.143 45.705 2.413 ;
     RECT  22.608 2.263 29.862 2.489 ;
     RECT  22.932 2.489 29.862 3.379 ;
     RECT  22.752 3.379 29.862 3.437 ;
     RECT  23.184 3.437 29.862 3.605 ;
     RECT  23.544 3.605 29.862 3.749 ;
     RECT  23.832 3.749 29.862 3.955 ;
     RECT  23.832 3.955 30.114 4.109 ;
     RECT  26.1 4.109 27.198 4.145 ;
     RECT  27.936 4.109 30.114 4.181 ;
     RECT  28.008 4.181 30.114 4.261 ;
     RECT  26.1 4.145 27.054 4.289 ;
     RECT  28.008 4.261 30.546 4.289 ;
     RECT  28.152 4.289 30.546 4.379 ;
     RECT  23.976 4.109 25.326 4.415 ;
     RECT  26.172 4.289 27.054 4.415 ;
     RECT  2.415 2.413 2.697 10.555 ;
     RECT  2.304 10.555 2.697 10.597 ;
     RECT  2.304 10.597 3.294 10.625 ;
     RECT  2.34 10.625 3.294 10.633 ;
     RECT  4.068 10.597 4.086 10.633 ;
     RECT  25.272 4.415 25.326 10.741 ;
     RECT  25.272 10.741 25.434 10.877 ;
     RECT  2.34 10.633 4.086 11.011 ;
     RECT  5.22 10.741 5.238 11.137 ;
     RECT  2.34 11.011 4.266 11.165 ;
     RECT  5.22 11.137 5.67 11.173 ;
     RECT  3.816 11.165 4.266 11.209 ;
     RECT  5.22 11.173 5.814 11.209 ;
     RECT  3.816 11.209 5.814 11.281 ;
     RECT  2.34 11.165 3.078 11.407 ;
     RECT  7.815 2.413 8.097 11.551 ;
     RECT  2.304 11.407 3.078 11.669 ;
     RECT  3.816 11.281 6.354 11.677 ;
     RECT  3.816 11.677 6.678 11.713 ;
     RECT  3.816 11.713 6.822 11.821 ;
     RECT  7.815 11.551 8.262 11.821 ;
     RECT  3.816 11.821 8.262 11.939 ;
     RECT  2.304 11.669 2.697 11.975 ;
     RECT  3.816 11.939 8.154 11.975 ;
     RECT  9.288 11.911 9.306 12.019 ;
     RECT  23.976 4.415 24.462 12.047 ;
     RECT  9.036 12.019 9.306 12.055 ;
     RECT  8.928 12.055 9.306 12.209 ;
     RECT  7.128 11.975 8.154 12.269 ;
     RECT  26.604 4.415 27.054 12.427 ;
     RECT  26.604 12.427 27.306 12.479 ;
     RECT  2.412 11.975 2.697 12.595 ;
     RECT  3.816 11.975 6.354 12.595 ;
     RECT  2.412 12.595 6.354 12.715 ;
     RECT  13.215 2.413 13.497 12.865 ;
     RECT  14.364 12.721 14.382 12.865 ;
     RECT  13.215 12.865 14.382 13.019 ;
     RECT  13.215 13.019 13.662 13.289 ;
     RECT  2.304 12.715 6.354 13.291 ;
     RECT  7.128 12.269 8.097 13.291 ;
     RECT  2.304 13.291 8.097 13.331 ;
     RECT  9.036 12.209 9.306 13.531 ;
     RECT  13.215 13.289 13.554 13.661 ;
     RECT  9.036 13.531 9.342 13.675 ;
     RECT  8.928 13.675 9.342 13.829 ;
     RECT  2.304 13.331 6.354 14.405 ;
     RECT  3.816 14.405 6.354 14.881 ;
     RECT  7.128 13.331 8.097 14.881 ;
     RECT  3.816 14.881 8.097 15.179 ;
     RECT  9.036 13.829 9.342 15.331 ;
     RECT  7.128 15.179 8.097 15.403 ;
     RECT  8.928 15.331 9.342 15.601 ;
     RECT  2.304 14.405 2.697 15.787 ;
     RECT  3.816 15.179 6.354 15.787 ;
     RECT  7.128 15.403 8.19 16.105 ;
     RECT  8.928 15.601 9.522 16.105 ;
     RECT  2.304 15.787 6.354 16.295 ;
     RECT  2.415 16.295 6.354 16.507 ;
     RECT  7.128 16.105 9.522 16.507 ;
     RECT  2.415 16.507 9.522 16.799 ;
     RECT  2.415 16.799 2.697 17.035 ;
     RECT  2.304 17.035 2.697 17.105 ;
     RECT  3.816 16.799 9.522 17.339 ;
     RECT  2.415 17.105 2.697 17.611 ;
     RECT  3.816 17.339 6.354 17.611 ;
     RECT  2.415 17.611 6.354 18.185 ;
     RECT  2.415 18.185 2.697 18.331 ;
     RECT  3.816 18.185 6.354 18.427 ;
     RECT  7.128 17.339 9.522 18.427 ;
     RECT  2.304 18.331 2.697 18.455 ;
     RECT  3.816 18.427 9.522 18.845 ;
     RECT  2.415 18.455 2.697 19.195 ;
     RECT  2.304 19.195 2.697 19.237 ;
     RECT  3.816 18.845 6.354 19.237 ;
     RECT  2.304 19.237 6.354 19.661 ;
     RECT  2.415 19.661 6.354 19.805 ;
     RECT  3.852 19.805 6.354 19.963 ;
     RECT  7.128 18.845 9.522 19.963 ;
     RECT  2.415 19.805 2.754 20.093 ;
     RECT  3.852 19.963 9.522 20.111 ;
     RECT  2.415 20.093 2.697 20.491 ;
     RECT  2.304 20.491 2.697 20.615 ;
     RECT  3.852 20.111 6.354 20.623 ;
     RECT  2.415 20.615 2.697 21.001 ;
     RECT  3.42 20.623 6.354 21.001 ;
     RECT  2.415 21.001 6.354 21.155 ;
     RECT  3.996 21.155 6.354 21.235 ;
     RECT  7.128 20.111 9.522 21.235 ;
     RECT  2.415 21.155 2.79 21.355 ;
     RECT  2.304 21.355 2.79 21.389 ;
     RECT  2.304 21.389 2.697 21.425 ;
     RECT  3.996 21.235 9.522 22.009 ;
     RECT  3.744 22.009 9.522 22.219 ;
     RECT  0.108 22.207 0.126 22.253 ;
     RECT  2.415 21.425 2.697 22.651 ;
     RECT  2.304 22.651 2.697 22.795 ;
     RECT  3.42 22.219 9.522 22.795 ;
     RECT  2.304 22.795 9.522 23.153 ;
     RECT  2.304 23.153 2.697 23.585 ;
     RECT  0.108 23.899 0.126 23.981 ;
     RECT  3.564 23.153 9.522 24.125 ;
     RECT  5.688 24.125 9.522 24.269 ;
     RECT  3.564 24.125 4.95 24.331 ;
     RECT  2.415 23.585 2.697 24.367 ;
     RECT  3.456 24.331 4.95 24.472 ;
     RECT  49.32 24.331 49.338 24.475 ;
     RECT  2.304 24.367 2.697 24.511 ;
     RECT  3.42 24.472 4.95 24.511 ;
     RECT  49.104 24.475 49.338 24.601 ;
     RECT  2.304 24.511 4.95 24.665 ;
     RECT  48.888 24.601 49.338 24.701 ;
     RECT  47.34 24.745 47.358 24.781 ;
     RECT  50.724 24.475 50.742 24.781 ;
     RECT  50.724 24.781 50.778 24.845 ;
     RECT  47.34 24.781 48.006 24.871 ;
     RECT  46.692 24.871 48.006 24.899 ;
     RECT  2.304 24.665 2.697 24.935 ;
     RECT  5.724 24.269 9.522 25.015 ;
     RECT  45.615 2.413 45.897 25.015 ;
     RECT  46.692 24.899 47.502 25.015 ;
     RECT  5.688 25.015 9.522 25.169 ;
     RECT  45.615 25.015 47.502 25.169 ;
     RECT  49.32 24.701 49.338 25.169 ;
     RECT  50.76 24.845 50.778 25.277 ;
     RECT  47.484 25.169 47.502 25.439 ;
     RECT  45.615 25.169 46.53 25.477 ;
     RECT  2.412 24.935 2.697 25.675 ;
     RECT  5.76 25.169 9.522 25.709 ;
     RECT  33.12 25.411 33.138 25.709 ;
     RECT  50.724 25.591 50.742 25.709 ;
     RECT  2.304 25.675 2.697 25.745 ;
     RECT  34.815 2.413 35.097 25.951 ;
     RECT  43.344 25.483 43.362 26.059 ;
     RECT  43.344 26.059 43.902 26.095 ;
     RECT  43.344 26.095 44.298 26.131 ;
     RECT  45.54 25.477 46.53 26.131 ;
     RECT  49.176 25.555 49.194 26.221 ;
     RECT  3.42 24.665 4.95 26.237 ;
     RECT  43.344 26.131 46.53 26.249 ;
     RECT  50.688 26.107 50.706 26.249 ;
     RECT  43.344 26.249 43.902 26.257 ;
     RECT  3.456 26.237 4.95 26.285 ;
     RECT  42.372 26.203 42.39 26.285 ;
     RECT  44.784 26.249 46.53 26.285 ;
     RECT  23.976 12.047 24.426 26.293 ;
     RECT  25.272 10.877 25.326 26.293 ;
     RECT  28.224 4.379 30.546 26.293 ;
     RECT  31.464 25.861 31.482 26.293 ;
     RECT  43.164 26.257 43.902 26.293 ;
     RECT  48.456 26.221 49.338 26.321 ;
     RECT  23.976 26.293 25.326 26.333 ;
     RECT  48.456 26.321 49.302 26.401 ;
     RECT  25.164 26.333 25.326 26.435 ;
     RECT  48.024 26.401 49.302 26.491 ;
     RECT  42.516 26.293 43.902 26.519 ;
     RECT  33.408 26.401 33.426 26.527 ;
     RECT  42.912 26.519 43.902 26.555 ;
     RECT  45.036 26.285 46.53 26.563 ;
     RECT  42.912 26.555 42.93 26.627 ;
     RECT  43.884 26.555 43.902 26.627 ;
     RECT  5.76 25.709 9.198 26.635 ;
     RECT  3.564 26.285 4.95 26.671 ;
     RECT  5.688 26.635 9.198 26.671 ;
     RECT  45.036 26.563 46.746 26.671 ;
     RECT  47.916 26.491 49.302 26.671 ;
     RECT  34.632 25.951 35.097 26.761 ;
     RECT  3.564 26.671 9.198 26.789 ;
     RECT  45.036 26.671 49.302 26.825 ;
     RECT  2.415 25.745 2.697 26.971 ;
     RECT  50.652 26.539 50.67 26.971 ;
     RECT  50.652 26.971 50.706 27.059 ;
     RECT  5.76 26.789 9.198 27.067 ;
     RECT  10.116 26.941 10.134 27.067 ;
     RECT  2.304 26.971 2.697 27.095 ;
     RECT  5.76 27.067 10.134 27.095 ;
     RECT  45.216 26.825 49.302 27.095 ;
     RECT  45.216 27.095 49.086 27.149 ;
     RECT  45.615 27.149 49.086 27.329 ;
     RECT  50.688 27.059 50.706 27.329 ;
     RECT  45.615 27.329 46.53 27.365 ;
     RECT  47.88 27.329 47.898 27.365 ;
     RECT  49.068 27.329 49.086 27.365 ;
     RECT  0.108 27.337 0.126 27.437 ;
     RECT  2.415 27.095 2.697 27.835 ;
     RECT  2.304 27.835 2.697 27.877 ;
     RECT  3.564 26.789 4.95 27.877 ;
     RECT  2.304 27.877 4.95 27.905 ;
     RECT  2.415 27.905 4.95 28.409 ;
     RECT  3.564 28.409 4.95 28.417 ;
     RECT  5.76 27.095 9.882 28.417 ;
     RECT  2.415 28.409 2.697 28.687 ;
     RECT  3.564 28.417 9.882 28.985 ;
     RECT  2.412 28.687 2.697 29.131 ;
     RECT  2.304 29.131 2.697 29.875 ;
     RECT  3.564 28.985 4.95 29.875 ;
     RECT  2.304 29.875 4.95 30.037 ;
     RECT  5.796 28.985 9.882 30.037 ;
     RECT  2.304 30.037 9.882 30.335 ;
     RECT  2.304 30.335 2.697 30.461 ;
     RECT  2.415 30.461 2.697 31.291 ;
     RECT  2.304 31.291 2.697 31.415 ;
     RECT  2.415 31.415 2.697 31.483 ;
     RECT  3.564 30.335 4.95 31.483 ;
     RECT  2.415 31.483 4.95 31.531 ;
     RECT  5.796 30.335 9.882 31.531 ;
     RECT  2.415 31.531 9.882 31.649 ;
     RECT  2.415 31.649 4.95 31.685 ;
     RECT  2.415 31.685 2.697 32.155 ;
     RECT  5.688 31.649 9.882 32.225 ;
     RECT  3.564 31.685 4.95 32.467 ;
     RECT  5.796 32.225 9.882 32.567 ;
     RECT  2.304 32.155 2.697 33.115 ;
     RECT  3.564 32.467 5.058 33.115 ;
     RECT  2.304 33.115 5.058 33.655 ;
     RECT  6.012 32.567 9.882 33.655 ;
     RECT  2.304 33.655 9.882 33.809 ;
     RECT  2.304 33.809 5.058 33.953 ;
     RECT  5.796 33.809 9.882 33.989 ;
     RECT  2.412 33.953 5.058 34.385 ;
     RECT  2.415 34.385 5.058 34.693 ;
     RECT  5.796 33.989 6.57 34.693 ;
     RECT  7.308 33.989 9.882 34.727 ;
     RECT  2.415 34.693 6.57 34.925 ;
     RECT  3.636 34.925 6.57 35.005 ;
     RECT  7.308 34.727 8.097 35.005 ;
     RECT  2.415 34.925 2.697 35.167 ;
     RECT  3.636 35.005 8.097 35.465 ;
     RECT  2.412 35.167 2.697 35.611 ;
     RECT  2.304 35.611 2.697 35.735 ;
     RECT  8.892 34.727 9.882 35.851 ;
     RECT  4.5 35.465 8.097 35.977 ;
     RECT  8.82 35.851 9.882 35.977 ;
     RECT  18.615 2.413 18.897 36.121 ;
     RECT  4.5 35.977 9.882 36.275 ;
     RECT  8.82 36.275 9.882 36.347 ;
     RECT  2.415 35.735 2.697 36.475 ;
     RECT  2.304 36.475 2.697 36.517 ;
     RECT  3.636 35.465 3.654 36.517 ;
     RECT  4.5 36.275 8.097 36.517 ;
     RECT  2.304 36.517 8.097 36.545 ;
     RECT  25.272 26.435 25.326 36.779 ;
     RECT  28.224 26.293 31.482 36.823 ;
     RECT  28.224 36.823 31.662 36.895 ;
     RECT  23.976 26.333 24.426 36.931 ;
     RECT  25.272 36.779 25.29 36.931 ;
     RECT  2.415 36.545 8.097 37.085 ;
     RECT  4.572 37.085 8.097 37.291 ;
     RECT  8.856 36.347 9.882 37.291 ;
     RECT  4.572 37.291 9.882 37.319 ;
     RECT  2.415 37.085 2.826 37.373 ;
     RECT  6.372 37.319 9.882 37.625 ;
     RECT  2.415 37.373 2.697 37.771 ;
     RECT  28.224 36.895 31.77 37.859 ;
     RECT  28.224 37.859 31.662 37.939 ;
     RECT  3.636 37.085 3.654 38.011 ;
     RECT  4.572 37.319 5.634 38.011 ;
     RECT  28.116 37.939 31.662 38.137 ;
     RECT  3.636 38.011 5.634 38.479 ;
     RECT  6.372 37.625 6.39 38.479 ;
     RECT  2.304 37.771 2.697 38.515 ;
     RECT  3.636 38.479 6.39 38.515 ;
     RECT  7.488 37.625 9.882 38.515 ;
     RECT  28.08 38.137 31.662 38.515 ;
     RECT  26.604 12.479 27.054 38.635 ;
     RECT  28.008 38.515 31.662 38.669 ;
     RECT  2.304 38.515 9.882 38.705 ;
     RECT  3.636 38.705 9.882 38.741 ;
     RECT  28.08 38.669 31.662 38.779 ;
     RECT  3.636 38.741 9.27 38.975 ;
     RECT  26.532 38.635 27.054 39.091 ;
     RECT  28.08 38.779 31.842 39.091 ;
     RECT  32.904 26.527 33.426 39.091 ;
     RECT  23.976 36.931 25.29 39.361 ;
     RECT  26.208 39.091 27.054 39.361 ;
     RECT  23.976 39.361 27.054 39.389 ;
     RECT  2.415 38.705 2.862 39.487 ;
     RECT  13.215 13.661 13.497 39.631 ;
     RECT  28.08 39.091 33.426 39.721 ;
     RECT  13.212 39.631 13.497 39.749 ;
     RECT  24.015 39.389 27.054 39.865 ;
     RECT  27.936 39.721 33.426 39.865 ;
     RECT  14.796 39.757 14.814 39.893 ;
     RECT  2.412 39.487 2.862 39.931 ;
     RECT  2.304 39.931 2.862 40.055 ;
     RECT  3.636 38.975 3.654 40.099 ;
     RECT  4.572 38.975 9.27 40.099 ;
     RECT  2.34 40.055 2.862 40.123 ;
     RECT  3.636 40.099 9.27 40.123 ;
     RECT  2.34 40.123 9.27 40.135 ;
     RECT  2.34 40.135 9.486 40.325 ;
     RECT  21.708 38.479 21.726 40.369 ;
     RECT  18.144 36.121 18.897 40.441 ;
     RECT  3.636 40.325 9.486 40.469 ;
     RECT  14.292 39.901 14.31 40.559 ;
     RECT  3.636 40.469 9.27 40.595 ;
     RECT  24.015 39.865 33.426 40.595 ;
     RECT  6.156 40.595 8.514 40.667 ;
     RECT  20.592 39.757 20.61 40.711 ;
     RECT  2.34 40.325 2.697 40.795 ;
     RECT  3.636 40.595 5.166 40.829 ;
     RECT  33.156 40.595 33.426 40.829 ;
     RECT  2.304 40.795 2.697 40.865 ;
     RECT  3.636 40.829 3.87 40.865 ;
     RECT  24.015 40.595 32.13 40.865 ;
     RECT  32.04 40.865 32.13 41.009 ;
     RECT  6.228 40.667 8.514 41.099 ;
     RECT  2.412 40.865 2.697 41.405 ;
     RECT  5.112 40.829 5.166 41.521 ;
     RECT  6.696 41.099 8.514 41.647 ;
     RECT  9.252 40.595 9.27 41.647 ;
     RECT  6.696 41.647 9.27 41.917 ;
     RECT  6.192 41.917 9.27 41.945 ;
     RECT  24.015 40.865 31.302 41.953 ;
     RECT  6.192 41.945 8.19 41.981 ;
     RECT  23.976 41.953 31.302 41.989 ;
     RECT  14.832 41.917 14.85 42.017 ;
     RECT  5.112 41.521 5.454 42.061 ;
     RECT  6.192 41.981 6.966 42.061 ;
     RECT  23.4 41.989 31.302 42.173 ;
     RECT  5.112 42.061 6.966 42.179 ;
     RECT  7.776 41.981 8.19 42.179 ;
     RECT  5.112 42.179 6.21 42.215 ;
     RECT  23.508 42.173 31.302 42.223 ;
     RECT  32.112 41.009 32.13 42.223 ;
     RECT  33.408 40.829 33.426 42.223 ;
     RECT  33.408 42.223 33.678 42.259 ;
     RECT  23.508 42.223 32.13 42.295 ;
     RECT  21.708 40.369 22.446 42.331 ;
     RECT  33.372 42.259 33.678 42.331 ;
     RECT  5.112 42.215 5.742 42.449 ;
     RECT  33.264 42.331 33.678 42.449 ;
     RECT  23.508 42.295 32.31 42.493 ;
     RECT  33.264 42.449 33.498 42.493 ;
     RECT  20.124 40.711 20.61 42.565 ;
     RECT  20.016 42.565 20.61 42.691 ;
     RECT  21.708 42.331 22.554 42.691 ;
     RECT  20.016 42.691 22.554 42.791 ;
     RECT  6.948 42.179 6.966 42.989 ;
     RECT  23.508 42.493 33.498 43.105 ;
     RECT  23.472 43.105 33.498 43.295 ;
     RECT  32.976 43.295 33.498 43.579 ;
     RECT  23.472 43.295 32.238 43.613 ;
     RECT  23.472 43.613 31.734 43.645 ;
     RECT  18.144 40.441 18.954 43.771 ;
     RECT  23.436 43.645 31.734 43.843 ;
     RECT  32.976 43.579 33.75 43.853 ;
     RECT  18.144 43.771 19.206 43.879 ;
     RECT  20.016 42.791 21.726 43.879 ;
     RECT  23.4 43.843 31.734 44.149 ;
     RECT  33.732 43.853 33.75 44.177 ;
     RECT  7.815 42.179 8.19 44.419 ;
     RECT  23.328 44.149 31.734 44.443 ;
     RECT  32.976 43.853 32.994 44.491 ;
     RECT  32.832 44.491 32.994 44.617 ;
     RECT  22.5 42.791 22.554 44.761 ;
     RECT  23.328 44.443 31.878 44.761 ;
     RECT  32.688 44.617 32.994 44.761 ;
     RECT  5.112 42.449 5.13 44.851 ;
     RECT  34.596 26.761 35.097 44.879 ;
     RECT  32.688 44.761 33.174 44.923 ;
     RECT  3.636 40.865 3.654 44.951 ;
     RECT  32.688 44.923 33.21 44.959 ;
     RECT  22.5 44.761 31.878 44.971 ;
     RECT  32.616 44.959 33.21 44.971 ;
     RECT  22.5 44.971 33.21 44.995 ;
     RECT  5.112 44.851 5.418 45.115 ;
     RECT  6.876 45.031 6.894 45.157 ;
     RECT  9.252 41.945 9.27 45.157 ;
     RECT  5.112 45.115 5.598 45.193 ;
     RECT  6.336 45.157 6.894 45.193 ;
     RECT  7.815 44.419 8.406 45.257 ;
     RECT  9.252 45.157 9.342 45.257 ;
     RECT  22.5 44.995 33.246 45.293 ;
     RECT  3.924 45.115 3.942 45.301 ;
     RECT  5.112 45.193 6.894 45.301 ;
     RECT  3.924 45.301 4.086 45.419 ;
     RECT  5.112 45.301 6.93 45.427 ;
     RECT  5.112 45.427 7.002 45.455 ;
     RECT  5.112 45.455 5.778 45.527 ;
     RECT  6.912 45.455 7.002 45.527 ;
     RECT  3.924 45.419 3.942 45.563 ;
     RECT  5.76 45.527 5.778 45.563 ;
     RECT  6.984 45.527 7.002 45.563 ;
     RECT  4.716 45.535 4.734 45.689 ;
     RECT  9.144 45.265 9.162 45.689 ;
     RECT  16.776 45.157 16.794 45.691 ;
     RECT  16.776 45.691 17.262 45.731 ;
     RECT  18.144 43.879 21.726 45.733 ;
     RECT  22.5 45.293 31.734 45.733 ;
     RECT  18.144 45.733 31.734 45.761 ;
     RECT  18.144 45.761 22.554 45.841 ;
     RECT  15.48 45.805 15.498 46.031 ;
     RECT  23.292 45.761 31.734 46.069 ;
     RECT  17.568 45.841 22.554 46.265 ;
     RECT  23.292 46.069 31.842 46.741 ;
     RECT  32.616 45.293 33.246 46.741 ;
     RECT  23.292 46.741 33.246 46.769 ;
     RECT  16.776 45.731 16.794 46.777 ;
     RECT  17.568 46.265 22.518 46.777 ;
     RECT  23.292 46.769 33.03 46.841 ;
     RECT  16.776 46.777 22.518 46.913 ;
     RECT  23.292 46.841 30.906 47.039 ;
     RECT  34.815 44.879 35.097 47.083 ;
     RECT  16.812 46.913 22.518 47.155 ;
     RECT  23.292 47.039 30.798 47.155 ;
     RECT  36.972 46.795 36.99 47.353 ;
     RECT  36.792 47.353 36.99 47.425 ;
     RECT  34.776 47.083 35.097 47.461 ;
     RECT  36.792 47.425 37.566 47.579 ;
     RECT  31.68 46.841 33.03 47.695 ;
     RECT  34.776 47.461 35.514 47.695 ;
     RECT  36.792 47.579 36.954 47.695 ;
     RECT  31.68 47.695 33.246 47.731 ;
     RECT  16.812 47.155 30.798 47.821 ;
     RECT  31.68 47.731 33.678 47.821 ;
     RECT  36.576 47.695 36.954 47.821 ;
     RECT  34.524 47.695 35.514 47.851 ;
     RECT  36.288 47.821 36.954 47.851 ;
     RECT  16.812 47.821 33.678 47.893 ;
     RECT  34.524 47.851 36.954 47.899 ;
     RECT  16.704 47.893 33.678 47.965 ;
     RECT  34.416 47.899 36.954 47.965 ;
     RECT  15.48 47.731 15.93 48.001 ;
     RECT  16.704 47.965 36.954 48.001 ;
     RECT  15.48 48.001 36.954 48.235 ;
     RECT  15.3 48.235 36.954 48.461 ;
     RECT  15.408 48.461 36.954 48.775 ;
     RECT  14.508 48.427 14.526 48.811 ;
     RECT  14.508 48.811 14.67 48.929 ;
     RECT  14.508 48.929 14.526 48.965 ;
     RECT  15.408 48.775 36.99 49.379 ;
     RECT  2.415 41.405 2.697 49.427 ;
     RECT  7.815 45.257 8.097 49.427 ;
     RECT  13.215 39.749 13.497 49.427 ;
     RECT  40.215 2.413 40.497 49.427 ;
     RECT  45.615 27.365 45.897 49.427 ;
     RECT  15.48 49.379 36.99 49.469 ;
     RECT  15.48 49.469 25.578 49.505 ;
     RECT  26.496 49.469 35.082 49.505 ;
     RECT  35.964 49.469 36.882 49.505 ;
     RECT  15.984 49.505 25.578 49.517 ;
     RECT  26.496 49.505 30.294 49.517 ;
     RECT  31.248 49.505 35.082 49.517 ;
     RECT  35.964 49.505 36.486 49.541 ;
     RECT  15.984 49.517 16.038 49.565 ;
     RECT  21.348 49.517 25.578 49.565 ;
     RECT  26.496 49.517 27.918 49.565 ;
     RECT  31.248 49.517 31.266 49.565 ;
     RECT  15.984 49.565 16.002 49.577 ;
     RECT  16.92 49.517 20.286 49.577 ;
     RECT  21.348 49.565 21.366 49.577 ;
     RECT  22.104 49.565 25.578 49.577 ;
     RECT  26.856 49.565 27.918 49.577 ;
     RECT  28.908 49.517 30.294 49.577 ;
     RECT  32.04 49.517 32.598 49.577 ;
     RECT  33.336 49.517 33.894 49.577 ;
     RECT  34.74 49.517 35.082 49.577 ;
     RECT  36.036 49.541 36.486 49.577 ;
     RECT  2.415 49.427 2.505 49.697 ;
     RECT  7.815 49.427 7.905 49.697 ;
     RECT  13.215 49.427 13.305 49.697 ;
     RECT  23.832 49.577 24.105 49.697 ;
     RECT  29.415 49.577 30.294 49.697 ;
     RECT  34.74 49.577 34.905 49.697 ;
     RECT  40.215 49.427 40.305 49.697 ;
     RECT  45.615 49.427 45.705 49.697 ;
     RECT  18.216 49.577 18.774 49.805 ;
     RECT  29.592 49.697 30.294 49.805 ;
     RECT  34.74 49.697 34.758 49.853 ;
     RECT  18.216 49.805 18.234 50.765 ;
     RECT  22.104 49.577 22.122 50.765 ;
     RECT  23.832 49.697 23.85 50.765 ;
     RECT  25.56 49.577 25.578 50.765 ;
     RECT  27.252 49.577 27.27 50.765 ;
     RECT  36.468 49.577 36.486 50.765 ;
     RECT  30.276 49.805 30.294 51.725 ;
    LAYER M4 ;
     RECT  0.06 10.56 2.408 41.256 ;
     RECT  2.408 2.148 2.512 49.692 ;
     RECT  2.512 2.418 2.704 49.422 ;
     RECT  2.704 19.344 2.765 21 ;
     RECT  2.704 17.616 2.837 17.928 ;
     RECT  2.704 36.864 2.837 37.368 ;
     RECT  2.704 38.64 2.837 39.096 ;
     RECT  2.704 31.488 3.34 31.512 ;
     RECT  2.704 15.792 3.347 15.816 ;
     RECT  2.704 10.8 3.349 10.824 ;
     RECT  2.704 22.224 3.449 22.824 ;
     RECT  2.765 20.976 3.484 21 ;
     RECT  2.704 26.208 3.733 26.232 ;
     RECT  2.704 32.544 3.737 32.568 ;
     RECT  2.765 19.344 3.841 19.368 ;
     RECT  2.704 24.48 3.841 24.504 ;
     RECT  2.704 27.888 3.841 27.912 ;
     RECT  2.704 33.6 3.841 33.624 ;
     RECT  3.841 23.904 3.925 24.504 ;
     RECT  3.925 23.904 3.971 24.648 ;
     RECT  2.704 40.128 4.213 40.152 ;
     RECT  4.213 40.128 4.259 40.68 ;
     RECT  4.259 40.656 4.3 40.68 ;
     RECT  3.841 27.456 4.309 27.912 ;
     RECT  3.841 19.344 4.355 20.328 ;
     RECT  2.704 34.848 4.549 34.872 ;
     RECT  2.837 17.616 4.601 17.64 ;
     RECT  4.355 19.344 4.637 19.656 ;
     RECT  2.704 12.768 4.789 13.704 ;
     RECT  3.733 25.968 4.796 26.232 ;
     RECT  4.309 27.36 4.796 27.912 ;
     RECT  3.449 22.8 4.813 22.824 ;
     RECT  3.971 24.48 4.813 24.648 ;
     RECT  4.796 25.968 4.813 27.912 ;
     RECT  2.837 38.64 4.813 38.664 ;
     RECT  4.813 24.48 4.837 27.912 ;
     RECT  4.405 28.992 4.837 29.016 ;
     RECT  3.841 32.976 4.849 33.624 ;
     RECT  4.789 12.768 4.853 14.664 ;
     RECT  4.813 22.8 4.853 23.352 ;
     RECT  4.837 24.48 4.853 29.016 ;
     RECT  4.849 32.16 4.853 33.624 ;
     RECT  4.813 38.64 4.853 38.808 ;
     RECT  4.853 13.296 4.876 14.664 ;
     RECT  4.853 24.624 4.883 29.016 ;
     RECT  4.883 28.464 4.924 29.016 ;
     RECT  2.704 30 4.924 30.024 ;
     RECT  3.913 45.12 5.609 45.144 ;
     RECT  4.876 13.296 5.717 13.704 ;
     RECT  4.813 11.376 5.857 11.4 ;
     RECT  4.853 23.328 5.857 23.352 ;
     RECT  4.549 34.704 5.857 34.872 ;
     RECT  5.857 11.376 5.897 11.736 ;
     RECT  4.883 27.168 5.897 27.48 ;
     RECT  2.837 36.864 6.001 36.888 ;
     RECT  4.853 32.16 6.041 33 ;
     RECT  6.001 36.432 6.041 36.888 ;
     RECT  5.821 30.768 6.073 30.792 ;
     RECT  5.857 22.992 6.14 23.352 ;
     RECT  6.14 22.992 6.145 23.544 ;
     RECT  4.883 24.624 6.145 25.992 ;
     RECT  4.853 38.784 6.145 38.808 ;
     RECT  6.145 22.8 6.181 23.544 ;
     RECT  6.145 24.624 6.181 26.04 ;
     RECT  6.145 38.784 6.185 39.336 ;
     RECT  6.073 30.576 6.217 30.792 ;
     RECT  6.041 32.16 6.217 32.856 ;
     RECT  6.181 22.8 6.227 26.04 ;
     RECT  5.857 34.704 6.229 35.352 ;
     RECT  6.227 22.8 6.293 23.016 ;
     RECT  6.293 22.992 6.365 23.016 ;
     RECT  4.849 16.512 6.369 16.536 ;
     RECT  4.637 19.632 6.389 19.656 ;
     RECT  6.389 19.632 6.421 19.992 ;
     RECT  6.229 34.368 6.421 35.352 ;
     RECT  6.185 39.312 6.421 39.336 ;
     RECT  6.227 24.336 6.437 26.04 ;
     RECT  6.421 34.176 6.437 35.352 ;
     RECT  6.437 34.176 6.467 34.728 ;
     RECT  6.369 16.512 6.473 16.872 ;
     RECT  6.421 18.432 6.473 19.992 ;
     RECT  6.181 21.264 6.473 21.288 ;
     RECT  5.897 27.168 6.473 27.336 ;
     RECT  4.924 28.8 6.473 29.016 ;
     RECT  6.473 18.432 6.508 19.656 ;
     RECT  6.467 34.176 6.508 34.392 ;
     RECT  6.421 39.312 6.508 40.968 ;
     RECT  6.217 30.576 6.509 32.856 ;
     RECT  6.509 30.576 6.617 31.752 ;
     RECT  6.508 39.312 7.477 40.152 ;
     RECT  7.477 38.736 7.513 40.152 ;
     RECT  7.513 37.968 7.621 40.152 ;
     RECT  6.041 36.432 7.669 36.456 ;
     RECT  6.473 27.312 7.693 27.336 ;
     RECT  7.441 22.128 7.729 22.152 ;
     RECT  5.897 11.712 7.808 11.736 ;
     RECT  5.717 13.296 7.808 13.56 ;
     RECT  6.469 14.928 7.808 14.952 ;
     RECT  6.473 16.848 7.808 16.872 ;
     RECT  6.508 18.816 7.808 19.656 ;
     RECT  7.477 20.688 7.808 20.712 ;
     RECT  7.729 22.128 7.808 22.248 ;
     RECT  6.437 24.336 7.808 24.36 ;
     RECT  6.437 26.016 7.808 26.04 ;
     RECT  7.693 27.168 7.808 27.336 ;
     RECT  6.473 28.992 7.808 29.016 ;
     RECT  6.617 30.576 7.808 30.792 ;
     RECT  6.509 32.832 7.808 32.856 ;
     RECT  6.508 34.368 7.808 34.392 ;
     RECT  7.669 36.096 7.808 36.456 ;
     RECT  7.621 37.44 7.808 40.152 ;
     RECT  5.42 41.952 7.808 41.976 ;
     RECT  7.808 2.148 7.912 49.692 ;
     RECT  7.912 2.418 8.104 49.422 ;
     RECT  8.104 16.848 8.165 16.872 ;
     RECT  8.104 11.712 8.243 13.656 ;
     RECT  8.104 14.928 8.243 15.432 ;
     RECT  8.104 20.88 8.243 20.904 ;
     RECT  8.104 22.224 8.243 22.248 ;
     RECT  8.104 24.48 8.243 24.504 ;
     RECT  8.104 25.824 8.243 26.04 ;
     RECT  8.104 30.576 8.243 31.416 ;
     RECT  8.104 32.64 8.243 33.048 ;
     RECT  8.243 15.408 8.245 15.432 ;
     RECT  8.104 34.224 8.245 34.392 ;
     RECT  8.243 26.016 8.273 26.04 ;
     RECT  8.245 34.368 8.273 34.392 ;
     RECT  8.104 19.68 8.281 19.704 ;
     RECT  8.104 28.8 8.483 29.064 ;
     RECT  8.104 27.168 8.633 27.192 ;
     RECT  8.104 37.968 8.675 40.248 ;
     RECT  8.675 38.544 8.713 40.248 ;
     RECT  8.713 40.224 8.957 40.248 ;
     RECT  8.243 32.64 9.065 33 ;
     RECT  8.243 31.344 9.173 31.368 ;
     RECT  9.133 22.704 9.245 22.728 ;
     RECT  9.065 32.64 9.245 32.904 ;
     RECT  9.245 32.88 9.353 32.904 ;
     RECT  8.243 12.768 13.208 13.656 ;
     RECT  8.483 29.04 13.208 29.064 ;
     RECT  13.208 2.148 13.312 49.692 ;
     RECT  13.312 2.418 13.504 49.422 ;
     RECT  13.504 12.768 13.565 13.656 ;
     RECT  14.497 48.432 15.649 48.456 ;
     RECT  15.649 48.384 15.692 48.456 ;
     RECT  15.692 48.384 15.779 49.032 ;
     RECT  15.779 48.384 16.049 48.456 ;
     RECT  16.009 49.488 16.697 49.56 ;
     RECT  16.049 48.432 18.044 48.456 ;
     RECT  18.044 48.096 18.085 48.456 ;
     RECT  18.205 50.736 18.371 50.76 ;
     RECT  13.565 12.768 18.608 13.128 ;
     RECT  15.301 26.304 18.608 26.328 ;
     RECT  13.504 29.04 18.608 29.064 ;
     RECT  17.233 45.696 18.608 45.72 ;
     RECT  18.085 47.136 18.608 48.456 ;
     RECT  16.697 49.536 18.608 49.56 ;
     RECT  18.608 2.148 18.712 49.692 ;
     RECT  18.712 2.418 18.716 49.692 ;
     RECT  18.716 2.418 18.803 49.8 ;
     RECT  18.803 2.418 18.904 49.56 ;
     RECT  18.904 48.432 19.001 48.456 ;
     RECT  18.904 45.696 19.897 45.72 ;
     RECT  18.904 47.04 20.149 47.16 ;
     RECT  19.897 44.976 20.195 45.72 ;
     RECT  20.108 43.104 20.252 43.128 ;
     RECT  20.252 43.104 20.257 43.32 ;
     RECT  20.149 47.04 20.257 47.304 ;
     RECT  20.257 46.8 20.293 47.304 ;
     RECT  20.293 46.8 20.329 47.88 ;
     RECT  20.257 42.768 20.339 43.32 ;
     RECT  20.195 44.976 20.339 45 ;
     RECT  18.904 29.04 20.485 29.064 ;
     RECT  20.485 28.752 20.531 29.064 ;
     RECT  20.329 46.128 20.836 47.88 ;
     RECT  20.836 46.128 20.867 47.928 ;
     RECT  18.904 49.536 20.917 49.56 ;
     RECT  20.917 49.488 21.017 49.56 ;
     RECT  20.867 46.8 21.481 47.928 ;
     RECT  20.339 42.768 21.685 42.792 ;
     RECT  21.685 42.144 21.731 42.792 ;
     RECT  21.481 46.8 21.841 48.264 ;
     RECT  22.093 50.736 22.259 50.76 ;
     RECT  21.841 46.56 22.421 48.264 ;
     RECT  18.904 12.768 22.499 13.128 ;
     RECT  21.731 42.144 23.497 42.168 ;
     RECT  22.421 46.8 23.965 48.264 ;
     RECT  23.821 50.736 23.987 50.76 ;
     RECT  22.417 1.728 24.008 1.752 ;
     RECT  22.453 3.408 24.008 3.432 ;
     RECT  22.499 13.104 24.008 13.128 ;
     RECT  18.904 26.304 24.008 26.328 ;
     RECT  20.531 28.752 24.008 28.776 ;
     RECT  23.497 42.144 24.008 42.504 ;
     RECT  23.749 45.024 24.008 45.048 ;
     RECT  23.965 46.272 24.008 48.264 ;
     RECT  21.017 49.536 24.008 49.56 ;
     RECT  23.929 0.576 24.013 0.6 ;
     RECT  24.008 1.728 24.112 49.692 ;
     RECT  24.112 1.728 24.304 49.56 ;
     RECT  24.304 26.304 24.833 26.424 ;
     RECT  24.304 12.432 25.187 13.128 ;
     RECT  24.304 28.752 25.187 28.776 ;
     RECT  24.833 26.4 25.228 26.424 ;
     RECT  24.304 49.536 25.283 49.56 ;
     RECT  24.304 45.84 25.369 47.4 ;
     RECT  25.369 45.84 25.409 47.928 ;
     RECT  24.304 42.48 25.484 43.272 ;
     RECT  25.405 10.752 25.489 10.872 ;
     RECT  25.484 42.48 25.549 44.136 ;
     RECT  25.549 41.568 25.571 44.136 ;
     RECT  25.409 45.984 25.571 47.928 ;
     RECT  25.571 45.984 25.715 47.448 ;
     RECT  25.549 50.736 25.715 50.76 ;
     RECT  25.715 46.224 25.805 47.448 ;
     RECT  24.304 40.32 25.909 40.344 ;
     RECT  25.805 46.512 26.129 47.448 ;
     RECT  25.909 39.552 26.197 40.344 ;
     RECT  26.101 49.344 26.201 49.368 ;
     RECT  25.571 43.248 26.305 44.136 ;
     RECT  26.197 39.552 26.521 40.392 ;
     RECT  26.305 43.248 26.597 44.712 ;
     RECT  25.801 3.936 26.693 3.96 ;
     RECT  25.571 41.568 26.701 41.592 ;
     RECT  26.597 43.248 26.701 43.32 ;
     RECT  26.701 41.568 26.741 43.32 ;
     RECT  26.521 38.64 26.771 40.392 ;
     RECT  26.693 3.312 26.777 3.96 ;
     RECT  26.771 40.032 26.813 40.392 ;
     RECT  25.489 10.848 26.924 10.872 ;
     RECT  26.924 10.56 27.011 10.872 ;
     RECT  25.187 12.432 27.317 12.456 ;
     RECT  26.777 3.936 27.349 3.96 ;
     RECT  27.241 50.736 27.443 50.76 ;
     RECT  26.597 44.64 27.529 44.712 ;
     RECT  26.741 42.432 27.637 43.32 ;
     RECT  27.529 44.64 27.637 45.048 ;
     RECT  27.637 42.432 27.683 45.048 ;
     RECT  27.349 3.936 27.884 4.008 ;
     RECT  27.884 3.408 27.971 4.008 ;
     RECT  27.683 42.432 28.001 44.712 ;
     RECT  26.813 40.032 28.037 40.344 ;
     RECT  28.001 42.432 28.037 44.088 ;
     RECT  26.129 46.512 28.037 47.4 ;
     RECT  28.037 42.432 28.105 42.744 ;
     RECT  28.037 40.32 28.217 40.344 ;
     RECT  26.485 49.536 28.261 49.56 ;
     RECT  28.037 46.512 28.361 47.112 ;
     RECT  24.304 1.728 29.197 1.752 ;
     RECT  28.361 46.752 29.257 47.112 ;
     RECT  28.393 48.384 29.257 48.408 ;
     RECT  28.105 42.24 29.269 42.744 ;
     RECT  27.971 3.936 29.408 4.008 ;
     RECT  28.761 12.24 29.408 12.264 ;
     RECT  29.269 24.912 29.408 24.936 ;
     RECT  26.771 38.688 29.408 38.76 ;
     RECT  29.269 41.664 29.408 42.744 ;
     RECT  28.037 44.064 29.408 44.088 ;
     RECT  29.257 46.752 29.408 48.408 ;
     RECT  28.261 49.488 29.408 49.56 ;
     RECT  29.408 2.148 29.512 49.692 ;
     RECT  29.512 2.418 29.557 49.692 ;
     RECT  29.557 2.418 29.644 49.8 ;
     RECT  29.644 2.418 29.704 49.56 ;
     RECT  29.704 46.8 29.765 49.56 ;
     RECT  29.765 48.384 30.035 49.56 ;
     RECT  29.704 38.16 30.269 39.816 ;
     RECT  29.704 44.592 30.341 45 ;
     RECT  29.704 36.912 30.515 37.08 ;
     RECT  30.035 48.384 30.521 49.368 ;
     RECT  30.269 38.16 30.593 39.432 ;
     RECT  30.593 38.16 30.707 39.24 ;
     RECT  30.341 44.976 30.737 45 ;
     RECT  29.765 46.8 30.757 47.208 ;
     RECT  30.521 48.384 30.769 48.408 ;
     RECT  30.707 38.688 30.803 39.24 ;
     RECT  30.757 46.8 30.805 47.304 ;
     RECT  29.704 42.24 30.853 42.84 ;
     RECT  30.803 38.736 30.899 39.24 ;
     RECT  30.265 51.696 30.899 51.72 ;
     RECT  30.853 42.24 30.901 43.224 ;
     RECT  30.805 46.272 30.901 47.304 ;
     RECT  30.899 38.784 30.94 39.24 ;
     RECT  30.901 42.24 30.997 43.32 ;
     RECT  30.997 41.28 31.025 43.848 ;
     RECT  30.901 45.6 31.043 47.304 ;
     RECT  31.025 41.28 31.093 42.264 ;
     RECT  31.093 40.464 31.133 42.264 ;
     RECT  31.133 41.568 31.139 42.264 ;
     RECT  31.139 42.24 31.529 42.264 ;
     RECT  31.133 40.464 31.601 40.488 ;
     RECT  31.237 49.536 31.717 49.56 ;
     RECT  30.769 48.336 31.817 48.408 ;
     RECT  31.717 49.488 31.817 49.56 ;
     RECT  31.025 43.824 31.849 43.848 ;
     RECT  31.043 45.6 31.849 47.112 ;
     RECT  30.94 38.784 31.853 38.808 ;
     RECT  31.817 48.336 31.889 48.36 ;
     RECT  31.849 43.824 32.053 47.112 ;
     RECT  32.053 43.824 32.099 47.928 ;
     RECT  32.099 43.824 32.197 44.472 ;
     RECT  32.197 43.584 32.243 44.472 ;
     RECT  32.099 46.752 32.645 47.928 ;
     RECT  31.817 49.536 33.013 49.56 ;
     RECT  33.013 49.488 33.1 49.56 ;
     RECT  32.243 43.584 33.689 43.848 ;
     RECT  33.689 43.584 33.761 43.608 ;
     RECT  33.1 49.536 34.309 49.56 ;
     RECT  34.309 49.488 34.7 49.56 ;
     RECT  34.7 49.488 34.787 49.848 ;
     RECT  29.704 12.24 34.808 12.264 ;
     RECT  29.704 24.912 34.808 24.936 ;
     RECT  29.704 27.12 34.808 27.144 ;
     RECT  32.645 46.8 34.808 47.928 ;
     RECT  34.787 49.488 34.808 49.692 ;
     RECT  34.808 2.148 34.912 49.692 ;
     RECT  34.912 2.418 35.104 49.56 ;
     RECT  35.104 47.856 35.165 47.928 ;
     RECT  35.104 49.344 35.705 49.56 ;
     RECT  35.705 49.536 36.083 49.56 ;
     RECT  36.428 50.736 36.515 50.76 ;
     RECT  35.165 47.856 36.605 47.88 ;
     RECT  35.104 46.8 37.001 46.824 ;
     RECT  35.104 12.24 40.208 12.264 ;
     RECT  35.104 24.912 40.208 24.936 ;
     RECT  35.104 27.12 40.208 27.144 ;
     RECT  40.208 2.148 40.312 49.692 ;
     RECT  40.312 2.418 40.504 49.422 ;
     RECT  40.504 27.12 42.361 27.144 ;
     RECT  40.504 12.24 42.467 12.264 ;
     RECT  40.504 24.912 43.333 24.936 ;
     RECT  42.361 26.208 43.333 27.144 ;
     RECT  43.333 24.912 43.373 27.144 ;
     RECT  43.373 24.912 45.608 25.512 ;
     RECT  43.373 27.12 45.608 27.144 ;
     RECT  45.608 2.148 45.712 49.692 ;
     RECT  45.712 2.418 45.904 49.422 ;
     RECT  45.904 24.912 46.499 25.512 ;
     RECT  45.904 26.784 46.499 26.808 ;
     RECT  46.499 24.912 46.541 25.08 ;
     RECT  46.541 24.912 46.721 24.936 ;
     RECT  50.641 26.544 50.677 26.568 ;
     RECT  50.677 26.112 50.713 27 ;
     RECT  50.713 24.816 51.804 27 ;
    LAYER M5 ;
     RECT  22.656 0.016 29.16 1.763 ;
     RECT  2.4 2.137 2.52 2.151 ;
     RECT  7.8 2.137 7.92 2.151 ;
     RECT  13.2 2.137 13.32 2.151 ;
     RECT  18.6 2.137 18.72 2.151 ;
     RECT  29.4 2.137 29.52 2.151 ;
     RECT  34.8 2.137 34.92 2.151 ;
     RECT  40.2 2.137 40.32 2.151 ;
     RECT  45.6 2.137 45.72 2.151 ;
     RECT  26.736 3.301 26.76 3.925 ;
     RECT  27.936 3.397 27.96 3.925 ;
     RECT  29.4 2.151 29.712 3.925 ;
     RECT  26.736 3.925 29.712 4.019 ;
     RECT  2.4 2.151 2.712 10.789 ;
     RECT  26.736 4.019 27 10.883 ;
     RECT  7.8 2.151 8.112 11.701 ;
     RECT  28.8 4.019 29.712 12.275 ;
     RECT  24 1.763 24.312 12.421 ;
     RECT  25.44 10.741 25.464 12.421 ;
     RECT  24 12.421 25.464 12.467 ;
     RECT  22.464 3.397 22.488 12.803 ;
     RECT  4.8 12.757 4.824 14.675 ;
     RECT  7.8 11.701 8.232 15.443 ;
     RECT  2.4 10.789 3.336 17.605 ;
     RECT  2.4 17.605 4.008 17.651 ;
     RECT  7.8 15.443 8.112 19.669 ;
     RECT  6.432 16.837 6.456 20.003 ;
     RECT  3.984 17.651 4.008 20.293 ;
     RECT  2.4 17.651 2.712 20.965 ;
     RECT  3.984 20.293 4.344 20.965 ;
     RECT  2.4 20.965 4.344 22.259 ;
     RECT  7.8 19.669 8.232 22.259 ;
     RECT  6.192 21.253 6.216 23.555 ;
     RECT  4.32 22.259 4.344 23.893 ;
     RECT  7.8 22.259 8.112 24.469 ;
     RECT  3.936 23.893 4.344 24.659 ;
     RECT  29.4 12.275 29.712 24.901 ;
     RECT  45.6 2.151 45.912 25.045 ;
     RECT  42.432 12.229 42.456 26.243 ;
     RECT  4.32 24.659 4.344 26.773 ;
     RECT  45.6 25.045 46.488 26.819 ;
     RECT  29.28 24.901 29.712 27.109 ;
     RECT  7.8 24.469 8.232 27.203 ;
     RECT  4.32 26.773 4.872 27.395 ;
     RECT  24 12.467 25.176 28.787 ;
     RECT  7.8 27.203 8.112 28.789 ;
     RECT  4.416 27.395 4.872 29.027 ;
     RECT  20.496 28.741 20.52 29.029 ;
     RECT  7.8 28.789 8.472 29.075 ;
     RECT  20.16 29.029 20.52 29.075 ;
     RECT  2.4 22.259 2.712 29.989 ;
     RECT  4.848 29.027 4.872 30.035 ;
     RECT  2.4 29.989 3.288 32.579 ;
     RECT  6.432 34.165 6.456 34.357 ;
     RECT  6.24 34.357 6.456 34.739 ;
     RECT  4.56 33.589 4.584 34.835 ;
     RECT  6.24 34.739 6.264 34.835 ;
     RECT  7.8 29.075 8.376 36.085 ;
     RECT  29.28 27.109 30.504 37.091 ;
     RECT  7.68 36.085 8.376 37.429 ;
     RECT  7.632 37.429 8.376 37.957 ;
     RECT  29.28 37.091 29.712 38.149 ;
     RECT  29.28 38.149 30.696 38.677 ;
     RECT  29.28 38.677 30.792 38.723 ;
     RECT  30.768 38.723 30.792 38.725 ;
     RECT  7.632 37.957 8.664 38.771 ;
     RECT  30.768 38.725 30.888 38.819 ;
     RECT  7.8 38.771 8.664 39.395 ;
     RECT  26.736 10.883 26.76 39.541 ;
     RECT  25.92 39.541 26.76 39.587 ;
     RECT  4.224 38.629 4.248 40.691 ;
     RECT  30.864 38.819 30.888 41.269 ;
     RECT  30.864 41.269 31.032 41.557 ;
     RECT  29.28 38.723 29.712 41.699 ;
     RECT  6.432 39.829 6.456 41.941 ;
     RECT  5.472 41.941 6.456 41.987 ;
     RECT  30.864 41.557 31.128 42.275 ;
     RECT  25.92 39.587 25.944 42.469 ;
     RECT  21.696 42.133 21.72 42.803 ;
     RECT  30.864 42.275 31.032 43.235 ;
     RECT  25.536 42.469 25.944 43.283 ;
     RECT  20.16 29.075 20.184 43.285 ;
     RECT  32.208 43.573 32.232 44.483 ;
     RECT  27.648 43.573 27.672 45.059 ;
     RECT  5.472 41.987 5.496 45.155 ;
     RECT  30.912 43.235 31.032 45.635 ;
     RECT  20.16 43.285 20.328 46.117 ;
     RECT  25.536 43.283 25.704 46.259 ;
     RECT  18.6 2.151 18.912 47.125 ;
     RECT  31.008 45.635 31.032 47.173 ;
     RECT  20.16 46.117 20.856 47.315 ;
     RECT  30.768 47.173 31.032 47.315 ;
     RECT  20.304 47.315 20.856 47.603 ;
     RECT  32.064 45.253 32.088 47.843 ;
     RECT  20.304 47.603 20.328 47.891 ;
     RECT  25.536 46.259 25.56 47.939 ;
     RECT  18.096 47.125 18.912 48.131 ;
     RECT  15.312 26.293 15.336 48.997 ;
     RECT  29.4 41.699 29.712 49.333 ;
     RECT  34.8 2.151 35.112 49.333 ;
     RECT  15.312 48.997 15.768 49.477 ;
     RECT  29.4 49.333 30.456 49.477 ;
     RECT  34.8 49.333 35.64 49.477 ;
     RECT  15.312 49.477 16.632 49.525 ;
     RECT  18.6 48.131 18.912 49.525 ;
     RECT  20.928 49.477 20.952 49.525 ;
     RECT  24 28.787 24.312 49.525 ;
     RECT  26.112 49.333 26.136 49.525 ;
     RECT  28.272 49.477 30.456 49.525 ;
     RECT  31.728 49.477 31.752 49.525 ;
     RECT  33.024 49.477 33.048 49.525 ;
     RECT  34.32 49.477 35.64 49.525 ;
     RECT  2.4 32.579 2.712 49.689 ;
     RECT  7.8 39.395 8.112 49.689 ;
     RECT  13.2 2.151 13.512 49.689 ;
     RECT  40.2 2.151 40.512 49.689 ;
     RECT  45.6 26.819 45.912 49.689 ;
     RECT  2.4 49.689 2.52 49.703 ;
     RECT  7.8 49.689 7.92 49.703 ;
     RECT  13.2 49.689 13.32 49.703 ;
     RECT  40.2 49.689 40.32 49.703 ;
     RECT  45.6 49.689 45.72 49.703 ;
     RECT  15.312 49.525 36.072 50.725 ;
     RECT  15.312 50.725 36.504 51.792 ;
     RECT  22.488 3.397 24 12.803 ;
     RECT  26.76 3.397 27.936 3.925 ;
     RECT  27.96 3.397 29.4 3.925 ;
     RECT  24.312 10.741 25.44 12.421 ;
     RECT  25.464 10.741 26.736 12.467 ;
     RECT  3.336 12.757 4.8 14.675 ;
     RECT  6.456 16.837 7.8 20.003 ;
     RECT  2.712 17.651 3.984 20.965 ;
     RECT  2.712 23.893 3.936 24.659 ;
     RECT  18.912 29.029 20.16 47.315 ;
     RECT  6.456 34.165 7.8 34.739 ;
     RECT  6.264 34.739 7.8 34.835 ;
     RECT  7.68 34.835 7.8 36.085 ;
     RECT  29.712 37.091 30.504 38.149 ;
     RECT  2.712 38.629 4.224 40.691 ;
     RECT  29.712 38.723 30.768 38.819 ;
     RECT  7.632 38.771 7.8 39.829 ;
     RECT  29.712 38.819 30.864 43.235 ;
     RECT  6.456 39.829 7.8 41.987 ;
     RECT  20.184 42.133 21.696 42.803 ;
     RECT  31.032 42.275 31.128 43.573 ;
     RECT  24.312 42.469 25.536 47.939 ;
     RECT  20.184 42.803 20.328 43.285 ;
     RECT  29.712 43.235 30.912 45.635 ;
     RECT  31.032 43.573 32.208 44.483 ;
     RECT  31.032 44.483 32.088 45.253 ;
     RECT  31.032 45.253 32.064 47.315 ;
     RECT  29.712 45.635 31.008 47.173 ;
     RECT  29.712 47.173 30.768 47.315 ;
     RECT  18.912 47.315 20.304 47.891 ;
     RECT  18.096 48.131 18.6 49.477 ;
     RECT  16.632 49.477 18.6 49.525 ;
     RECT  30.456 49.477 31.728 49.525 ;
     RECT  31.752 49.477 33.024 49.525 ;
     RECT  33.048 49.477 34.32 49.525 ;
  END
END dsfd_vm_static_read_v5_p
END LIBRARY
